# Copyright (c) 1993 - 2025 ARM Limited. All Rights Reserved.
# Use of this Software is subject to the terms and conditions of the
# applicable license agreement with ARM Limited.

# PhyVGen V 11.0.0-beta2
# ARM Version r3p1
# Creation Date: Fri Jan 31 07:21:36 2025


# Memory Configuration:
# ~~~~~~~~~~~~~~~~~~~~~
#  -PG_PINS_domain VDDCE -activity_factor 50 -atf off -back_biasing off
# -bit_blast off -bits 46 -bmux off -check_instname on -diodes on -drive 6 -ema
# on -frequency 500 -instname sram128x46 -left_bus_delim "[" -mux 2 -mvt BASE
# -name_case lower -power_gating off -power_type otc -pwr_gnd_rename
# vddpe:VDDPE,vddce:VDDCE,vsse:VSSE -rcols 2 -redundancy off -retention on
# -right_bus_delim "]" -rrows 0 -ser none -single_domain_only on -site_def off
# -top_layer m5-m10 -vmin_assist on -words 128 -wp_size 1 -write_mask off
# -write_thru off -corners
# ffg_cbestt_0p88v_0p88v_0c,ffg_cbestt_0p88v_0p88v_125c,ffg_cbestt_0p88v_0p88v_m40c,ssg_cworstt_0p72v_0p72v_0c,ssg_cworstt_0p72v_0p72v_125c,ssg_cworstt_0p72v_0p72v_m40c,tt_typical_0p80v_0p80v_25c,tt_typical_0p80v_0p80v_85c
# 

VERSION 5.8 ;
BUSBITCHARS "[]" ;
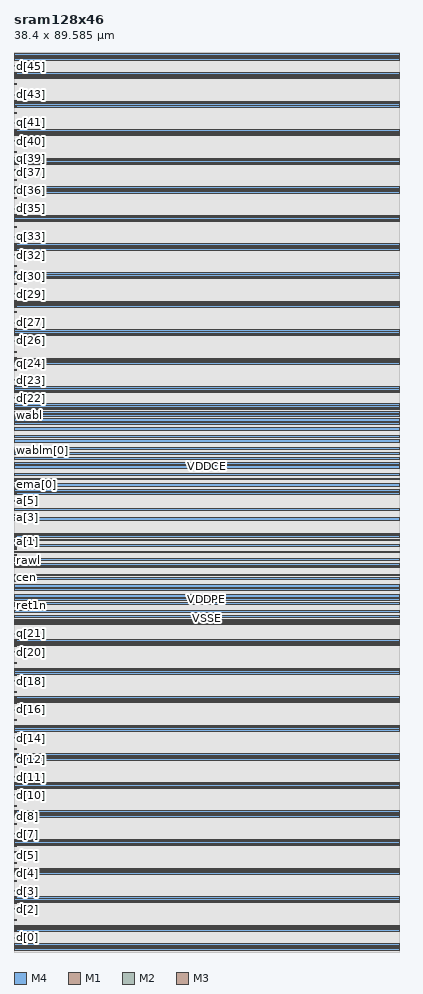
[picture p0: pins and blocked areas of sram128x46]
MACRO sram128x46
	FOREIGN sram128x46 0 0 ;
	SYMMETRY X Y ;
	SIZE 38.4 BY 89.585 ;
	CLASS BLOCK ;
	PIN VDDCE
		USE POWER ;
		DIRECTION INOUT ;
		PORT
			LAYER	M4 ;
			RECT	0 36.325 38.4 36.535 ;
		END

		PORT
			LAYER	M4 ;
			RECT	0 48.175 38.4 48.385 ;
		END

		PORT
			LAYER	M4 ;
			RECT	0 50.035 38.4 50.185 ;
		END

		PORT
			LAYER	M4 ;
			RECT	0 53.64 38.4 53.79 ;
		END

		PORT
			LAYER	M4 ;
			RECT	0 87.135 38.4 87.285 ;
		END

		PORT
			LAYER	M4 ;
			RECT	0 25.02 38.4 25.17 ;
		END

		PORT
			LAYER	M4 ;
			RECT	0 22.18 38.4 22.33 ;
		END

		PORT
			LAYER	M4 ;
			RECT	0 19.34 38.4 19.49 ;
		END

		PORT
			LAYER	M4 ;
			RECT	0 16.5 38.4 16.65 ;
		END

		PORT
			LAYER	M4 ;
			RECT	0 13.66 38.4 13.81 ;
		END

		PORT
			LAYER	M4 ;
			RECT	0 81.455 38.4 81.605 ;
		END

		PORT
			LAYER	M4 ;
			RECT	0 10.82 38.4 10.97 ;
		END

		PORT
			LAYER	M4 ;
			RECT	0 7.98 38.4 8.13 ;
		END

		PORT
			LAYER	M4 ;
			RECT	0 5.14 38.4 5.29 ;
		END

		PORT
			LAYER	M4 ;
			RECT	0 2.3 38.4 2.45 ;
		END

		PORT
			LAYER	M4 ;
			RECT	0 78.615 38.4 78.765 ;
		END

		PORT
			LAYER	M4 ;
			RECT	0 75.775 38.4 75.925 ;
		END

		PORT
			LAYER	M4 ;
			RECT	0 72.935 38.4 73.085 ;
		END

		PORT
			LAYER	M4 ;
			RECT	0 70.095 38.4 70.245 ;
		END

		PORT
			LAYER	M4 ;
			RECT	0 67.255 38.4 67.405 ;
		END

		PORT
			LAYER	M4 ;
			RECT	0 64.415 38.4 64.565 ;
		END

		PORT
			LAYER	M4 ;
			RECT	0 61.575 38.4 61.725 ;
		END

		PORT
			LAYER	M4 ;
			RECT	0 58.735 38.4 58.885 ;
		END

		PORT
			LAYER	M4 ;
			RECT	0 55.895 38.4 56.045 ;
		END

		PORT
			LAYER	M4 ;
			RECT	0 84.295 38.4 84.445 ;
		END

		PORT
			LAYER	M4 ;
			RECT	0 30.7 38.4 30.85 ;
		END

		PORT
			LAYER	M4 ;
			RECT	0 27.86 38.4 28.01 ;
		END

		PORT
			LAYER	M4 ;
			RECT	0 32.595 38.4 32.725 ;
		END

		PORT
			LAYER	M4 ;
			RECT	0 36.025 38.4 36.155 ;
		END

		PORT
			LAYER	M4 ;
			RECT	0 88.765 38.4 88.915 ;
		END

		PORT
			LAYER	M4 ;
			RECT	0 48.555 38.4 48.685 ;
		END

		PORT
			LAYER	M4 ;
			RECT	0 0.67 38.4 0.82 ;
		END

		PORT
			LAYER	M4 ;
			RECT	0 54.43 38.4 54.56 ;
		END

	END VDDCE

	PIN VDDPE
		USE POWER ;
		DIRECTION INOUT ;
		PORT
			LAYER	M4 ;
			RECT	0 34.615 38.4 34.765 ;
		END

		PORT
			LAYER	M4 ;
			RECT	0 34.985 38.4 35.195 ;
		END

		PORT
			LAYER	M4 ;
			RECT	0 38.51 38.4 38.72 ;
		END

		PORT
			LAYER	M4 ;
			RECT	0 38.985 38.4 39.195 ;
		END

		PORT
			LAYER	M4 ;
			RECT	0 40.4 38.4 40.61 ;
		END

		PORT
			LAYER	M4 ;
			RECT	0 41.545 38.4 41.695 ;
		END

		PORT
			LAYER	M4 ;
			RECT	0 43.96 38.4 44.17 ;
		END

		PORT
			LAYER	M4 ;
			RECT	0 45.52 38.4 45.73 ;
		END

		PORT
			LAYER	M4 ;
			RECT	0 46.38 38.4 46.59 ;
		END

		PORT
			LAYER	M4 ;
			RECT	0 49.49 38.4 49.7 ;
		END

		PORT
			LAYER	M4 ;
			RECT	0 52.47 38.4 52.68 ;
		END

		PORT
			LAYER	M4 ;
			RECT	0 52.845 38.4 53.055 ;
		END

		PORT
			LAYER	M4 ;
			RECT	0 86.905 38.4 87.055 ;
		END

		PORT
			LAYER	M4 ;
			RECT	0 25.25 38.4 25.4 ;
		END

		PORT
			LAYER	M4 ;
			RECT	0 22.41 38.4 22.56 ;
		END

		PORT
			LAYER	M4 ;
			RECT	0 19.57 38.4 19.72 ;
		END

		PORT
			LAYER	M4 ;
			RECT	0 16.73 38.4 16.88 ;
		END

		PORT
			LAYER	M4 ;
			RECT	0 13.89 38.4 14.04 ;
		END

		PORT
			LAYER	M4 ;
			RECT	0 11.05 38.4 11.2 ;
		END

		PORT
			LAYER	M4 ;
			RECT	0 8.21 38.4 8.36 ;
		END

		PORT
			LAYER	M4 ;
			RECT	0 81.225 38.4 81.375 ;
		END

		PORT
			LAYER	M4 ;
			RECT	0 5.37 38.4 5.52 ;
		END

		PORT
			LAYER	M4 ;
			RECT	0 2.53 38.4 2.68 ;
		END

		PORT
			LAYER	M4 ;
			RECT	0 78.385 38.4 78.535 ;
		END

		PORT
			LAYER	M4 ;
			RECT	0 75.545 38.4 75.695 ;
		END

		PORT
			LAYER	M4 ;
			RECT	0 72.705 38.4 72.855 ;
		END

		PORT
			LAYER	M4 ;
			RECT	0 69.865 38.4 70.015 ;
		END

		PORT
			LAYER	M4 ;
			RECT	0 67.025 38.4 67.175 ;
		END

		PORT
			LAYER	M4 ;
			RECT	0 64.185 38.4 64.335 ;
		END

		PORT
			LAYER	M4 ;
			RECT	0 61.345 38.4 61.495 ;
		END

		PORT
			LAYER	M4 ;
			RECT	0 58.505 38.4 58.655 ;
		END

		PORT
			LAYER	M4 ;
			RECT	0 55.665 38.4 55.815 ;
		END

		PORT
			LAYER	M4 ;
			RECT	0 84.065 38.4 84.215 ;
		END

		PORT
			LAYER	M4 ;
			RECT	0 30.93 38.4 31.08 ;
		END

		PORT
			LAYER	M4 ;
			RECT	0 28.09 38.4 28.24 ;
		END

		PORT
			LAYER	M4 ;
			RECT	0 89.265 38.4 89.415 ;
		END

		PORT
			LAYER	M4 ;
			RECT	0 33.015 38.4 33.145 ;
		END

		PORT
			LAYER	M4 ;
			RECT	0 37.485 38.4 37.615 ;
		END

		PORT
			LAYER	M4 ;
			RECT	0 0.17 38.4 0.32 ;
		END

		PORT
			LAYER	M4 ;
			RECT	0 45.86 38.4 45.99 ;
		END

		PORT
			LAYER	M4 ;
			RECT	0 54.01 38.4 54.14 ;
		END

	END VDDPE

	PIN VSSE
		USE GROUND ;
		DIRECTION INOUT ;
		PORT
			LAYER	M4 ;
			RECT	0 32.805 38.4 32.935 ;
		END

		PORT
			LAYER	M4 ;
			RECT	0 89.015 38.4 89.165 ;
		END

		PORT
			LAYER	M4 ;
			RECT	0 39.785 38.4 39.915 ;
		END

		PORT
			LAYER	M4 ;
			RECT	0 0.42 38.4 0.57 ;
		END

		PORT
			LAYER	M4 ;
			RECT	0 47.05 38.4 47.18 ;
		END

		PORT
			LAYER	M4 ;
			RECT	0 51.245 38.4 51.375 ;
		END

		PORT
			LAYER	M4 ;
			RECT	0 54.22 38.4 54.35 ;
		END

		PORT
			LAYER	M4 ;
			RECT	0 33.34 38.4 33.47 ;
		END

		PORT
			LAYER	M4 ;
			RECT	0 33.75 38.4 33.96 ;
		END

		PORT
			LAYER	M4 ;
			RECT	0 35.33 38.4 35.54 ;
		END

		PORT
			LAYER	M4 ;
			RECT	0 37.12 38.4 37.27 ;
		END

		PORT
			LAYER	M4 ;
			RECT	0 38.225 38.4 38.375 ;
		END

		PORT
			LAYER	M4 ;
			RECT	0 40.935 38.4 41.085 ;
		END

		PORT
			LAYER	M4 ;
			RECT	0 41.275 38.4 41.425 ;
		END

		PORT
			LAYER	M4 ;
			RECT	0 42.99 38.4 43.2 ;
		END

		PORT
			LAYER	M4 ;
			RECT	0 47.41 38.4 47.62 ;
		END

		PORT
			LAYER	M4 ;
			RECT	0 49.015 38.4 49.225 ;
		END

		PORT
			LAYER	M4 ;
			RECT	0 50.755 38.4 50.965 ;
		END

		PORT
			LAYER	M4 ;
			RECT	0 51.95 38.4 52.16 ;
		END

		PORT
			LAYER	M4 ;
			RECT	0 53.315 38.4 53.525 ;
		END

		PORT
			LAYER	M4 ;
			RECT	0 87.365 38.4 87.515 ;
		END

		PORT
			LAYER	M4 ;
			RECT	0 27.63 38.4 27.78 ;
		END

		PORT
			LAYER	M4 ;
			RECT	0 24.79 38.4 24.94 ;
		END

		PORT
			LAYER	M4 ;
			RECT	0 21.95 38.4 22.1 ;
		END

		PORT
			LAYER	M4 ;
			RECT	0 81.685 38.4 81.835 ;
		END

		PORT
			LAYER	M4 ;
			RECT	0 19.11 38.4 19.26 ;
		END

		PORT
			LAYER	M4 ;
			RECT	0 16.27 38.4 16.42 ;
		END

		PORT
			LAYER	M4 ;
			RECT	0 13.43 38.4 13.58 ;
		END

		PORT
			LAYER	M4 ;
			RECT	0 10.59 38.4 10.74 ;
		END

		PORT
			LAYER	M4 ;
			RECT	0 7.75 38.4 7.9 ;
		END

		PORT
			LAYER	M4 ;
			RECT	0 4.91 38.4 5.06 ;
		END

		PORT
			LAYER	M4 ;
			RECT	0 2.07 38.4 2.22 ;
		END

		PORT
			LAYER	M4 ;
			RECT	0 78.845 38.4 78.995 ;
		END

		PORT
			LAYER	M4 ;
			RECT	0 76.005 38.4 76.155 ;
		END

		PORT
			LAYER	M4 ;
			RECT	0 73.165 38.4 73.315 ;
		END

		PORT
			LAYER	M4 ;
			RECT	0 70.325 38.4 70.475 ;
		END

		PORT
			LAYER	M4 ;
			RECT	0 67.485 38.4 67.635 ;
		END

		PORT
			LAYER	M4 ;
			RECT	0 64.645 38.4 64.795 ;
		END

		PORT
			LAYER	M4 ;
			RECT	0 61.805 38.4 61.955 ;
		END

		PORT
			LAYER	M4 ;
			RECT	0 58.965 38.4 59.115 ;
		END

		PORT
			LAYER	M4 ;
			RECT	0 56.125 38.4 56.275 ;
		END

		PORT
			LAYER	M4 ;
			RECT	0 84.525 38.4 84.675 ;
		END

		PORT
			LAYER	M4 ;
			RECT	0 30.47 38.4 30.62 ;
		END

	END VSSE

	PIN a[0]
		USE SIGNAL ;
		DIRECTION INPUT ;
		SHAPE ABUTMENT ;
		PORT
			LAYER	M1 ;
			RECT	0 52.745 0.25 52.845 ;
			LAYER	M2 ;
			RECT	0 52.745 0.25 52.845 ;
			LAYER	M3 ;
			RECT	0 52.745 0.25 52.845 ;
		END

		ANTENNAGATEAREA 0.014 ;
		ANTENNADIFFAREA 0.018 ;
		ANTENNAPARTIALMETALAREA 0.025 ;
	END a[0]

	PIN a[1]
		USE SIGNAL ;
		DIRECTION INPUT ;
		SHAPE ABUTMENT ;
		PORT
			LAYER	M1 ;
			RECT	0 40.85 0.25 40.95 ;
			LAYER	M2 ;
			RECT	0 40.85 0.25 40.95 ;
			LAYER	M3 ;
			RECT	0 40.85 0.25 40.95 ;
		END

		ANTENNAGATEAREA 0.014 ;
		ANTENNADIFFAREA 0.018 ;
		ANTENNAPARTIALMETALAREA 0.025 ;
	END a[1]

	PIN a[2]
		USE SIGNAL ;
		DIRECTION INPUT ;
		SHAPE ABUTMENT ;
		PORT
			LAYER	M1 ;
			RECT	0 41.25 0.25 41.35 ;
			LAYER	M2 ;
			RECT	0 41.25 0.25 41.35 ;
			LAYER	M3 ;
			RECT	0 41.25 0.25 41.35 ;
		END

		ANTENNAGATEAREA 0.014 ;
		ANTENNADIFFAREA 0.018 ;
		ANTENNAPARTIALMETALAREA 0.025 ;
	END a[2]

	PIN a[3]
		USE SIGNAL ;
		DIRECTION INPUT ;
		SHAPE ABUTMENT ;
		PORT
			LAYER	M1 ;
			RECT	0 43.16 0.25 43.26 ;
			LAYER	M2 ;
			RECT	0 43.16 0.25 43.26 ;
			LAYER	M3 ;
			RECT	0 43.16 0.25 43.26 ;
		END

		ANTENNAGATEAREA 0.014 ;
		ANTENNADIFFAREA 0.018 ;
		ANTENNAPARTIALMETALAREA 0.025 ;
	END a[3]

	PIN a[4]
		USE SIGNAL ;
		DIRECTION INPUT ;
		SHAPE ABUTMENT ;
		PORT
			LAYER	M1 ;
			RECT	0 43.49 0.25 43.59 ;
			LAYER	M2 ;
			RECT	0 43.49 0.25 43.59 ;
			LAYER	M3 ;
			RECT	0 43.49 0.25 43.59 ;
		END

		ANTENNAGATEAREA 0.014 ;
		ANTENNADIFFAREA 0.018 ;
		ANTENNAPARTIALMETALAREA 0.025 ;
	END a[4]

	PIN a[5]
		USE SIGNAL ;
		DIRECTION INPUT ;
		SHAPE ABUTMENT ;
		PORT
			LAYER	M1 ;
			RECT	0 45.595 0.25 45.695 ;
			LAYER	M2 ;
			RECT	0 45.595 0.25 45.695 ;
			LAYER	M3 ;
			RECT	0 45.595 0.25 45.695 ;
		END

		ANTENNAGATEAREA 0.014 ;
		ANTENNADIFFAREA 0.018 ;
		ANTENNAPARTIALMETALAREA 0.025 ;
	END a[5]

	PIN a[6]
		USE SIGNAL ;
		DIRECTION INPUT ;
		SHAPE ABUTMENT ;
		PORT
			LAYER	M1 ;
			RECT	0 46.865 0.25 46.965 ;
			LAYER	M2 ;
			RECT	0 46.865 0.25 46.965 ;
			LAYER	M3 ;
			RECT	0 46.865 0.25 46.965 ;
		END

		ANTENNAGATEAREA 0.014 ;
		ANTENNADIFFAREA 0.018 ;
		ANTENNAPARTIALMETALAREA 0.025 ;
	END a[6]

	PIN cen
		USE SIGNAL ;
		DIRECTION INPUT ;
		SHAPE ABUTMENT ;
		PORT
			LAYER	M1 ;
			RECT	0 37.26 0.25 37.36 ;
			LAYER	M2 ;
			RECT	0 37.26 0.25 37.36 ;
			LAYER	M3 ;
			RECT	0 37.26 0.25 37.36 ;
		END

		ANTENNAGATEAREA 0.014 ;
		ANTENNADIFFAREA 0.018 ;
		ANTENNAPARTIALMETALAREA 0.025 ;
	END cen

	PIN clk
		USE SIGNAL ;
		DIRECTION INPUT ;
		SHAPE ABUTMENT ;
		PORT
			LAYER	M1 ;
			RECT	0 36.87 0.25 36.97 ;
			LAYER	M2 ;
			RECT	0 36.87 0.25 36.97 ;
			LAYER	M3 ;
			RECT	0 36.87 0.25 36.97 ;
			LAYER	M4 ;
			RECT	0 36.87 0.25 36.97 ;
		END

		ANTENNAGATEAREA 0.014 ;
		ANTENNADIFFAREA 0.018 ;
		ANTENNAPARTIALMETALAREA 0.025 ;
	END clk

	PIN d[0]
		USE SIGNAL ;
		DIRECTION INPUT ;
		SHAPE ABUTMENT ;
		PORT
			LAYER	M1 ;
			RECT	0 1.365 0.25 1.465 ;
			LAYER	M2 ;
			RECT	0 1.365 0.25 1.465 ;
			LAYER	M3 ;
			RECT	0 1.365 0.25 1.465 ;
		END

		ANTENNAGATEAREA 0.014 ;
		ANTENNADIFFAREA 0.018 ;
		ANTENNAPARTIALMETALAREA 0.025 ;
	END d[0]

	PIN d[10]
		USE SIGNAL ;
		DIRECTION INPUT ;
		SHAPE ABUTMENT ;
		PORT
			LAYER	M1 ;
			RECT	0 15.565 0.25 15.665 ;
			LAYER	M2 ;
			RECT	0 15.565 0.25 15.665 ;
			LAYER	M3 ;
			RECT	0 15.565 0.25 15.665 ;
		END

		ANTENNAGATEAREA 0.014 ;
		ANTENNADIFFAREA 0.018 ;
		ANTENNAPARTIALMETALAREA 0.025 ;
	END d[10]

	PIN d[11]
		USE SIGNAL ;
		DIRECTION INPUT ;
		SHAPE ABUTMENT ;
		PORT
			LAYER	M1 ;
			RECT	0 17.355 0.25 17.455 ;
			LAYER	M2 ;
			RECT	0 17.355 0.25 17.455 ;
			LAYER	M3 ;
			RECT	0 17.355 0.25 17.455 ;
		END

		ANTENNAGATEAREA 0.014 ;
		ANTENNADIFFAREA 0.018 ;
		ANTENNAPARTIALMETALAREA 0.025 ;
	END d[11]

	PIN d[12]
		USE SIGNAL ;
		DIRECTION INPUT ;
		SHAPE ABUTMENT ;
		PORT
			LAYER	M1 ;
			RECT	0 18.405 0.25 18.505 ;
			LAYER	M2 ;
			RECT	0 18.405 0.25 18.505 ;
			LAYER	M3 ;
			RECT	0 18.405 0.25 18.505 ;
		END

		ANTENNAGATEAREA 0.014 ;
		ANTENNADIFFAREA 0.018 ;
		ANTENNAPARTIALMETALAREA 0.025 ;
	END d[12]

	PIN d[13]
		USE SIGNAL ;
		DIRECTION INPUT ;
		SHAPE ABUTMENT ;
		PORT
			LAYER	M1 ;
			RECT	0 20.195 0.25 20.295 ;
			LAYER	M2 ;
			RECT	0 20.195 0.25 20.295 ;
			LAYER	M3 ;
			RECT	0 20.195 0.25 20.295 ;
		END

		ANTENNAGATEAREA 0.014 ;
		ANTENNADIFFAREA 0.018 ;
		ANTENNAPARTIALMETALAREA 0.025 ;
	END d[13]

	PIN d[14]
		USE SIGNAL ;
		DIRECTION INPUT ;
		SHAPE ABUTMENT ;
		PORT
			LAYER	M1 ;
			RECT	0 21.245 0.25 21.345 ;
			LAYER	M2 ;
			RECT	0 21.245 0.25 21.345 ;
			LAYER	M3 ;
			RECT	0 21.245 0.25 21.345 ;
		END

		ANTENNAGATEAREA 0.014 ;
		ANTENNADIFFAREA 0.018 ;
		ANTENNAPARTIALMETALAREA 0.025 ;
	END d[14]

	PIN d[15]
		USE SIGNAL ;
		DIRECTION INPUT ;
		SHAPE ABUTMENT ;
		PORT
			LAYER	M1 ;
			RECT	0 23.035 0.25 23.135 ;
			LAYER	M2 ;
			RECT	0 23.035 0.25 23.135 ;
			LAYER	M3 ;
			RECT	0 23.035 0.25 23.135 ;
		END

		ANTENNAGATEAREA 0.014 ;
		ANTENNADIFFAREA 0.018 ;
		ANTENNAPARTIALMETALAREA 0.025 ;
	END d[15]

	PIN d[16]
		USE SIGNAL ;
		DIRECTION INPUT ;
		SHAPE ABUTMENT ;
		PORT
			LAYER	M1 ;
			RECT	0 24.085 0.25 24.185 ;
			LAYER	M2 ;
			RECT	0 24.085 0.25 24.185 ;
			LAYER	M3 ;
			RECT	0 24.085 0.25 24.185 ;
		END

		ANTENNAGATEAREA 0.014 ;
		ANTENNADIFFAREA 0.018 ;
		ANTENNAPARTIALMETALAREA 0.025 ;
	END d[16]

	PIN d[17]
		USE SIGNAL ;
		DIRECTION INPUT ;
		SHAPE ABUTMENT ;
		PORT
			LAYER	M1 ;
			RECT	0 25.875 0.25 25.975 ;
			LAYER	M2 ;
			RECT	0 25.875 0.25 25.975 ;
			LAYER	M3 ;
			RECT	0 25.875 0.25 25.975 ;
		END

		ANTENNAGATEAREA 0.014 ;
		ANTENNADIFFAREA 0.018 ;
		ANTENNAPARTIALMETALAREA 0.025 ;
	END d[17]

	PIN d[18]
		USE SIGNAL ;
		DIRECTION INPUT ;
		SHAPE ABUTMENT ;
		PORT
			LAYER	M1 ;
			RECT	0 26.925 0.25 27.025 ;
			LAYER	M2 ;
			RECT	0 26.925 0.25 27.025 ;
			LAYER	M3 ;
			RECT	0 26.925 0.25 27.025 ;
		END

		ANTENNAGATEAREA 0.014 ;
		ANTENNADIFFAREA 0.018 ;
		ANTENNAPARTIALMETALAREA 0.025 ;
	END d[18]

	PIN d[19]
		USE SIGNAL ;
		DIRECTION INPUT ;
		SHAPE ABUTMENT ;
		PORT
			LAYER	M1 ;
			RECT	0 28.715 0.25 28.815 ;
			LAYER	M2 ;
			RECT	0 28.715 0.25 28.815 ;
			LAYER	M3 ;
			RECT	0 28.715 0.25 28.815 ;
		END

		ANTENNAGATEAREA 0.014 ;
		ANTENNADIFFAREA 0.018 ;
		ANTENNAPARTIALMETALAREA 0.025 ;
	END d[19]

	PIN d[1]
		USE SIGNAL ;
		DIRECTION INPUT ;
		SHAPE ABUTMENT ;
		PORT
			LAYER	M1 ;
			RECT	0 3.155 0.25 3.255 ;
			LAYER	M2 ;
			RECT	0 3.155 0.25 3.255 ;
			LAYER	M3 ;
			RECT	0 3.155 0.25 3.255 ;
		END

		ANTENNAGATEAREA 0.014 ;
		ANTENNADIFFAREA 0.018 ;
		ANTENNAPARTIALMETALAREA 0.025 ;
	END d[1]

	PIN d[20]
		USE SIGNAL ;
		DIRECTION INPUT ;
		SHAPE ABUTMENT ;
		PORT
			LAYER	M1 ;
			RECT	0 29.765 0.25 29.865 ;
			LAYER	M2 ;
			RECT	0 29.765 0.25 29.865 ;
			LAYER	M3 ;
			RECT	0 29.765 0.25 29.865 ;
		END

		ANTENNAGATEAREA 0.014 ;
		ANTENNADIFFAREA 0.018 ;
		ANTENNAPARTIALMETALAREA 0.025 ;
	END d[20]

	PIN d[21]
		USE SIGNAL ;
		DIRECTION INPUT ;
		SHAPE ABUTMENT ;
		PORT
			LAYER	M1 ;
			RECT	0 31.555 0.25 31.655 ;
			LAYER	M2 ;
			RECT	0 31.555 0.25 31.655 ;
			LAYER	M3 ;
			RECT	0 31.555 0.25 31.655 ;
		END

		ANTENNAGATEAREA 0.014 ;
		ANTENNADIFFAREA 0.018 ;
		ANTENNAPARTIALMETALAREA 0.025 ;
	END d[21]

	PIN d[22]
		USE SIGNAL ;
		DIRECTION INPUT ;
		SHAPE ABUTMENT ;
		PORT
			LAYER	M1 ;
			RECT	0 55.09 0.25 55.19 ;
			LAYER	M2 ;
			RECT	0 55.09 0.25 55.19 ;
			LAYER	M3 ;
			RECT	0 55.09 0.25 55.19 ;
		END

		ANTENNAGATEAREA 0.014 ;
		ANTENNADIFFAREA 0.018 ;
		ANTENNAPARTIALMETALAREA 0.025 ;
	END d[22]

	PIN d[23]
		USE SIGNAL ;
		DIRECTION INPUT ;
		SHAPE ABUTMENT ;
		PORT
			LAYER	M1 ;
			RECT	0 56.88 0.25 56.98 ;
			LAYER	M2 ;
			RECT	0 56.88 0.25 56.98 ;
			LAYER	M3 ;
			RECT	0 56.88 0.25 56.98 ;
		END

		ANTENNAGATEAREA 0.014 ;
		ANTENNADIFFAREA 0.018 ;
		ANTENNAPARTIALMETALAREA 0.025 ;
	END d[23]

	PIN d[24]
		USE SIGNAL ;
		DIRECTION INPUT ;
		SHAPE ABUTMENT ;
		PORT
			LAYER	M1 ;
			RECT	0 57.93 0.25 58.03 ;
			LAYER	M2 ;
			RECT	0 57.93 0.25 58.03 ;
			LAYER	M3 ;
			RECT	0 57.93 0.25 58.03 ;
		END

		ANTENNAGATEAREA 0.014 ;
		ANTENNADIFFAREA 0.018 ;
		ANTENNAPARTIALMETALAREA 0.025 ;
	END d[24]

	PIN d[25]
		USE SIGNAL ;
		DIRECTION INPUT ;
		SHAPE ABUTMENT ;
		PORT
			LAYER	M1 ;
			RECT	0 59.72 0.25 59.82 ;
			LAYER	M2 ;
			RECT	0 59.72 0.25 59.82 ;
			LAYER	M3 ;
			RECT	0 59.72 0.25 59.82 ;
		END

		ANTENNAGATEAREA 0.014 ;
		ANTENNADIFFAREA 0.018 ;
		ANTENNAPARTIALMETALAREA 0.025 ;
	END d[25]

	PIN d[26]
		USE SIGNAL ;
		DIRECTION INPUT ;
		SHAPE ABUTMENT ;
		PORT
			LAYER	M1 ;
			RECT	0 60.77 0.25 60.87 ;
			LAYER	M2 ;
			RECT	0 60.77 0.25 60.87 ;
			LAYER	M3 ;
			RECT	0 60.77 0.25 60.87 ;
		END

		ANTENNAGATEAREA 0.014 ;
		ANTENNADIFFAREA 0.018 ;
		ANTENNAPARTIALMETALAREA 0.025 ;
	END d[26]

	PIN d[27]
		USE SIGNAL ;
		DIRECTION INPUT ;
		SHAPE ABUTMENT ;
		PORT
			LAYER	M1 ;
			RECT	0 62.56 0.25 62.66 ;
			LAYER	M2 ;
			RECT	0 62.56 0.25 62.66 ;
			LAYER	M3 ;
			RECT	0 62.56 0.25 62.66 ;
		END

		ANTENNAGATEAREA 0.014 ;
		ANTENNADIFFAREA 0.018 ;
		ANTENNAPARTIALMETALAREA 0.025 ;
	END d[27]

	PIN d[28]
		USE SIGNAL ;
		DIRECTION INPUT ;
		SHAPE ABUTMENT ;
		PORT
			LAYER	M1 ;
			RECT	0 63.61 0.25 63.71 ;
			LAYER	M2 ;
			RECT	0 63.61 0.25 63.71 ;
			LAYER	M3 ;
			RECT	0 63.61 0.25 63.71 ;
		END

		ANTENNAGATEAREA 0.014 ;
		ANTENNADIFFAREA 0.018 ;
		ANTENNAPARTIALMETALAREA 0.025 ;
	END d[28]

	PIN d[29]
		USE SIGNAL ;
		DIRECTION INPUT ;
		SHAPE ABUTMENT ;
		PORT
			LAYER	M1 ;
			RECT	0 65.4 0.25 65.5 ;
			LAYER	M2 ;
			RECT	0 65.4 0.25 65.5 ;
			LAYER	M3 ;
			RECT	0 65.4 0.25 65.5 ;
		END

		ANTENNAGATEAREA 0.014 ;
		ANTENNADIFFAREA 0.018 ;
		ANTENNAPARTIALMETALAREA 0.025 ;
	END d[29]

	PIN d[2]
		USE SIGNAL ;
		DIRECTION INPUT ;
		SHAPE ABUTMENT ;
		PORT
			LAYER	M1 ;
			RECT	0 4.205 0.25 4.305 ;
			LAYER	M2 ;
			RECT	0 4.205 0.25 4.305 ;
			LAYER	M3 ;
			RECT	0 4.205 0.25 4.305 ;
		END

		ANTENNAGATEAREA 0.014 ;
		ANTENNADIFFAREA 0.018 ;
		ANTENNAPARTIALMETALAREA 0.025 ;
	END d[2]

	PIN d[30]
		USE SIGNAL ;
		DIRECTION INPUT ;
		SHAPE ABUTMENT ;
		PORT
			LAYER	M1 ;
			RECT	0 66.45 0.25 66.55 ;
			LAYER	M2 ;
			RECT	0 66.45 0.25 66.55 ;
			LAYER	M3 ;
			RECT	0 66.45 0.25 66.55 ;
		END

		ANTENNAGATEAREA 0.014 ;
		ANTENNADIFFAREA 0.018 ;
		ANTENNAPARTIALMETALAREA 0.025 ;
	END d[30]

	PIN d[31]
		USE SIGNAL ;
		DIRECTION INPUT ;
		SHAPE ABUTMENT ;
		PORT
			LAYER	M1 ;
			RECT	0 68.24 0.25 68.34 ;
			LAYER	M2 ;
			RECT	0 68.24 0.25 68.34 ;
			LAYER	M3 ;
			RECT	0 68.24 0.25 68.34 ;
		END

		ANTENNAGATEAREA 0.014 ;
		ANTENNADIFFAREA 0.018 ;
		ANTENNAPARTIALMETALAREA 0.025 ;
	END d[31]

	PIN d[32]
		USE SIGNAL ;
		DIRECTION INPUT ;
		SHAPE ABUTMENT ;
		PORT
			LAYER	M1 ;
			RECT	0 69.29 0.25 69.39 ;
			LAYER	M2 ;
			RECT	0 69.29 0.25 69.39 ;
			LAYER	M3 ;
			RECT	0 69.29 0.25 69.39 ;
		END

		ANTENNAGATEAREA 0.014 ;
		ANTENNADIFFAREA 0.018 ;
		ANTENNAPARTIALMETALAREA 0.025 ;
	END d[32]

	PIN d[33]
		USE SIGNAL ;
		DIRECTION INPUT ;
		SHAPE ABUTMENT ;
		PORT
			LAYER	M1 ;
			RECT	0 71.08 0.25 71.18 ;
			LAYER	M2 ;
			RECT	0 71.08 0.25 71.18 ;
			LAYER	M3 ;
			RECT	0 71.08 0.25 71.18 ;
		END

		ANTENNAGATEAREA 0.014 ;
		ANTENNADIFFAREA 0.018 ;
		ANTENNAPARTIALMETALAREA 0.025 ;
	END d[33]

	PIN d[34]
		USE SIGNAL ;
		DIRECTION INPUT ;
		SHAPE ABUTMENT ;
		PORT
			LAYER	M1 ;
			RECT	0 72.13 0.25 72.23 ;
			LAYER	M2 ;
			RECT	0 72.13 0.25 72.23 ;
			LAYER	M3 ;
			RECT	0 72.13 0.25 72.23 ;
		END

		ANTENNAGATEAREA 0.014 ;
		ANTENNADIFFAREA 0.018 ;
		ANTENNAPARTIALMETALAREA 0.025 ;
	END d[34]

	PIN d[35]
		USE SIGNAL ;
		DIRECTION INPUT ;
		SHAPE ABUTMENT ;
		PORT
			LAYER	M1 ;
			RECT	0 73.92 0.25 74.02 ;
			LAYER	M2 ;
			RECT	0 73.92 0.25 74.02 ;
			LAYER	M3 ;
			RECT	0 73.92 0.25 74.02 ;
		END

		ANTENNAGATEAREA 0.014 ;
		ANTENNADIFFAREA 0.018 ;
		ANTENNAPARTIALMETALAREA 0.025 ;
	END d[35]

	PIN d[36]
		USE SIGNAL ;
		DIRECTION INPUT ;
		SHAPE ABUTMENT ;
		PORT
			LAYER	M1 ;
			RECT	0 74.97 0.25 75.07 ;
			LAYER	M2 ;
			RECT	0 74.97 0.25 75.07 ;
			LAYER	M3 ;
			RECT	0 74.97 0.25 75.07 ;
		END

		ANTENNAGATEAREA 0.014 ;
		ANTENNADIFFAREA 0.018 ;
		ANTENNAPARTIALMETALAREA 0.025 ;
	END d[36]

	PIN d[37]
		USE SIGNAL ;
		DIRECTION INPUT ;
		SHAPE ABUTMENT ;
		PORT
			LAYER	M1 ;
			RECT	0 76.76 0.25 76.86 ;
			LAYER	M2 ;
			RECT	0 76.76 0.25 76.86 ;
			LAYER	M3 ;
			RECT	0 76.76 0.25 76.86 ;
		END

		ANTENNAGATEAREA 0.014 ;
		ANTENNADIFFAREA 0.018 ;
		ANTENNAPARTIALMETALAREA 0.025 ;
	END d[37]

	PIN d[38]
		USE SIGNAL ;
		DIRECTION INPUT ;
		SHAPE ABUTMENT ;
		PORT
			LAYER	M1 ;
			RECT	0 77.81 0.25 77.91 ;
			LAYER	M2 ;
			RECT	0 77.81 0.25 77.91 ;
			LAYER	M3 ;
			RECT	0 77.81 0.25 77.91 ;
		END

		ANTENNAGATEAREA 0.014 ;
		ANTENNADIFFAREA 0.018 ;
		ANTENNAPARTIALMETALAREA 0.025 ;
	END d[38]

	PIN d[39]
		USE SIGNAL ;
		DIRECTION INPUT ;
		SHAPE ABUTMENT ;
		PORT
			LAYER	M1 ;
			RECT	0 79.6 0.25 79.7 ;
			LAYER	M2 ;
			RECT	0 79.6 0.25 79.7 ;
			LAYER	M3 ;
			RECT	0 79.6 0.25 79.7 ;
		END

		ANTENNAGATEAREA 0.014 ;
		ANTENNADIFFAREA 0.018 ;
		ANTENNAPARTIALMETALAREA 0.025 ;
	END d[39]

	PIN d[3]
		USE SIGNAL ;
		DIRECTION INPUT ;
		SHAPE ABUTMENT ;
		PORT
			LAYER	M1 ;
			RECT	0 5.995 0.25 6.095 ;
			LAYER	M2 ;
			RECT	0 5.995 0.25 6.095 ;
			LAYER	M3 ;
			RECT	0 5.995 0.25 6.095 ;
		END

		ANTENNAGATEAREA 0.014 ;
		ANTENNADIFFAREA 0.018 ;
		ANTENNAPARTIALMETALAREA 0.025 ;
	END d[3]

	PIN d[40]
		USE SIGNAL ;
		DIRECTION INPUT ;
		SHAPE ABUTMENT ;
		PORT
			LAYER	M1 ;
			RECT	0 80.65 0.25 80.75 ;
			LAYER	M2 ;
			RECT	0 80.65 0.25 80.75 ;
			LAYER	M3 ;
			RECT	0 80.65 0.25 80.75 ;
		END

		ANTENNAGATEAREA 0.014 ;
		ANTENNADIFFAREA 0.018 ;
		ANTENNAPARTIALMETALAREA 0.025 ;
	END d[40]

	PIN d[41]
		USE SIGNAL ;
		DIRECTION INPUT ;
		SHAPE ABUTMENT ;
		PORT
			LAYER	M1 ;
			RECT	0 82.44 0.25 82.54 ;
			LAYER	M2 ;
			RECT	0 82.44 0.25 82.54 ;
			LAYER	M3 ;
			RECT	0 82.44 0.25 82.54 ;
		END

		ANTENNAGATEAREA 0.014 ;
		ANTENNADIFFAREA 0.018 ;
		ANTENNAPARTIALMETALAREA 0.025 ;
	END d[41]

	PIN d[42]
		USE SIGNAL ;
		DIRECTION INPUT ;
		SHAPE ABUTMENT ;
		PORT
			LAYER	M1 ;
			RECT	0 83.49 0.25 83.59 ;
			LAYER	M2 ;
			RECT	0 83.49 0.25 83.59 ;
			LAYER	M3 ;
			RECT	0 83.49 0.25 83.59 ;
		END

		ANTENNAGATEAREA 0.014 ;
		ANTENNADIFFAREA 0.018 ;
		ANTENNAPARTIALMETALAREA 0.025 ;
	END d[42]

	PIN d[43]
		USE SIGNAL ;
		DIRECTION INPUT ;
		SHAPE ABUTMENT ;
		PORT
			LAYER	M1 ;
			RECT	0 85.28 0.25 85.38 ;
			LAYER	M2 ;
			RECT	0 85.28 0.25 85.38 ;
			LAYER	M3 ;
			RECT	0 85.28 0.25 85.38 ;
		END

		ANTENNAGATEAREA 0.014 ;
		ANTENNADIFFAREA 0.018 ;
		ANTENNAPARTIALMETALAREA 0.025 ;
	END d[43]

	PIN d[44]
		USE SIGNAL ;
		DIRECTION INPUT ;
		SHAPE ABUTMENT ;
		PORT
			LAYER	M1 ;
			RECT	0 86.33 0.25 86.43 ;
			LAYER	M2 ;
			RECT	0 86.33 0.25 86.43 ;
			LAYER	M3 ;
			RECT	0 86.33 0.25 86.43 ;
		END

		ANTENNAGATEAREA 0.014 ;
		ANTENNADIFFAREA 0.018 ;
		ANTENNAPARTIALMETALAREA 0.025 ;
	END d[44]

	PIN d[45]
		USE SIGNAL ;
		DIRECTION INPUT ;
		SHAPE ABUTMENT ;
		PORT
			LAYER	M1 ;
			RECT	0 88.12 0.25 88.22 ;
			LAYER	M2 ;
			RECT	0 88.12 0.25 88.22 ;
			LAYER	M3 ;
			RECT	0 88.12 0.25 88.22 ;
		END

		ANTENNAGATEAREA 0.014 ;
		ANTENNADIFFAREA 0.018 ;
		ANTENNAPARTIALMETALAREA 0.025 ;
	END d[45]

	PIN d[4]
		USE SIGNAL ;
		DIRECTION INPUT ;
		SHAPE ABUTMENT ;
		PORT
			LAYER	M1 ;
			RECT	0 7.045 0.25 7.145 ;
			LAYER	M2 ;
			RECT	0 7.045 0.25 7.145 ;
			LAYER	M3 ;
			RECT	0 7.045 0.25 7.145 ;
		END

		ANTENNAGATEAREA 0.014 ;
		ANTENNADIFFAREA 0.018 ;
		ANTENNAPARTIALMETALAREA 0.025 ;
	END d[4]

	PIN d[5]
		USE SIGNAL ;
		DIRECTION INPUT ;
		SHAPE ABUTMENT ;
		PORT
			LAYER	M1 ;
			RECT	0 8.835 0.25 8.935 ;
			LAYER	M2 ;
			RECT	0 8.835 0.25 8.935 ;
			LAYER	M3 ;
			RECT	0 8.835 0.25 8.935 ;
		END

		ANTENNAGATEAREA 0.014 ;
		ANTENNADIFFAREA 0.018 ;
		ANTENNAPARTIALMETALAREA 0.025 ;
	END d[5]

	PIN d[6]
		USE SIGNAL ;
		DIRECTION INPUT ;
		SHAPE ABUTMENT ;
		PORT
			LAYER	M1 ;
			RECT	0 9.885 0.25 9.985 ;
			LAYER	M2 ;
			RECT	0 9.885 0.25 9.985 ;
			LAYER	M3 ;
			RECT	0 9.885 0.25 9.985 ;
		END

		ANTENNAGATEAREA 0.014 ;
		ANTENNADIFFAREA 0.018 ;
		ANTENNAPARTIALMETALAREA 0.025 ;
	END d[6]

	PIN d[7]
		USE SIGNAL ;
		DIRECTION INPUT ;
		SHAPE ABUTMENT ;
		PORT
			LAYER	M1 ;
			RECT	0 11.675 0.25 11.775 ;
			LAYER	M2 ;
			RECT	0 11.675 0.25 11.775 ;
			LAYER	M3 ;
			RECT	0 11.675 0.25 11.775 ;
		END

		ANTENNAGATEAREA 0.014 ;
		ANTENNADIFFAREA 0.018 ;
		ANTENNAPARTIALMETALAREA 0.025 ;
	END d[7]

	PIN d[8]
		USE SIGNAL ;
		DIRECTION INPUT ;
		SHAPE ABUTMENT ;
		PORT
			LAYER	M1 ;
			RECT	0 12.725 0.25 12.825 ;
			LAYER	M2 ;
			RECT	0 12.725 0.25 12.825 ;
			LAYER	M3 ;
			RECT	0 12.725 0.25 12.825 ;
		END

		ANTENNAGATEAREA 0.014 ;
		ANTENNADIFFAREA 0.018 ;
		ANTENNAPARTIALMETALAREA 0.025 ;
	END d[8]

	PIN d[9]
		USE SIGNAL ;
		DIRECTION INPUT ;
		SHAPE ABUTMENT ;
		PORT
			LAYER	M1 ;
			RECT	0 14.515 0.25 14.615 ;
			LAYER	M2 ;
			RECT	0 14.515 0.25 14.615 ;
			LAYER	M3 ;
			RECT	0 14.515 0.25 14.615 ;
		END

		ANTENNAGATEAREA 0.014 ;
		ANTENNADIFFAREA 0.018 ;
		ANTENNAPARTIALMETALAREA 0.025 ;
	END d[9]

	PIN ema[0]
		USE SIGNAL ;
		DIRECTION INPUT ;
		SHAPE ABUTMENT ;
		PORT
			LAYER	M1 ;
			RECT	0 46.465 0.25 46.565 ;
			LAYER	M2 ;
			RECT	0 46.465 0.25 46.565 ;
			LAYER	M3 ;
			RECT	0 46.465 0.25 46.565 ;
		END

		ANTENNAGATEAREA 0.014 ;
		ANTENNADIFFAREA 0.018 ;
		ANTENNAPARTIALMETALAREA 0.025 ;
	END ema[0]

	PIN ema[1]
		USE SIGNAL ;
		DIRECTION INPUT ;
		SHAPE ABUTMENT ;
		PORT
			LAYER	M1 ;
			RECT	0 46.265 0.25 46.365 ;
			LAYER	M2 ;
			RECT	0 46.265 0.25 46.365 ;
			LAYER	M3 ;
			RECT	0 46.265 0.25 46.365 ;
		END

		ANTENNAGATEAREA 0.014 ;
		ANTENNADIFFAREA 0.018 ;
		ANTENNAPARTIALMETALAREA 0.025 ;
	END ema[1]

	PIN ema[2]
		USE SIGNAL ;
		DIRECTION INPUT ;
		SHAPE ABUTMENT ;
		PORT
			LAYER	M1 ;
			RECT	0 46.065 0.25 46.165 ;
			LAYER	M2 ;
			RECT	0 46.065 0.25 46.165 ;
			LAYER	M3 ;
			RECT	0 46.065 0.25 46.165 ;
		END

		ANTENNAGATEAREA 0.014 ;
		ANTENNADIFFAREA 0.018 ;
		ANTENNAPARTIALMETALAREA 0.025 ;
	END ema[2]

	PIN emas
		USE SIGNAL ;
		DIRECTION INPUT ;
		SHAPE ABUTMENT ;
		PORT
			LAYER	M1 ;
			RECT	0 53.12 0.25 53.22 ;
			LAYER	M2 ;
			RECT	0 53.12 0.25 53.22 ;
			LAYER	M3 ;
			RECT	0 53.12 0.25 53.22 ;
		END

		ANTENNAGATEAREA 0.014 ;
		ANTENNADIFFAREA 0.018 ;
		ANTENNAPARTIALMETALAREA 0.025 ;
	END emas

	PIN emaw[0]
		USE SIGNAL ;
		DIRECTION INPUT ;
		SHAPE ABUTMENT ;
		PORT
			LAYER	M2 ;
			RECT	0 40.055 0.25 40.155 ;
			LAYER	M3 ;
			RECT	0 40.055 0.25 40.155 ;
		END

		ANTENNAGATEAREA 0.014 ;
		ANTENNADIFFAREA 0.018 ;
		ANTENNAPARTIALMETALAREA 0.025 ;
	END emaw[0]

	PIN emaw[1]
		USE SIGNAL ;
		DIRECTION INPUT ;
		SHAPE ABUTMENT ;
		PORT
			LAYER	M1 ;
			RECT	0 40.25 0.25 40.35 ;
			LAYER	M2 ;
			RECT	0 40.25 0.25 40.35 ;
			LAYER	M3 ;
			RECT	0 40.25 0.25 40.35 ;
		END

		ANTENNAGATEAREA 0.014 ;
		ANTENNADIFFAREA 0.018 ;
		ANTENNAPARTIALMETALAREA 0.025 ;
	END emaw[1]

	PIN q[0]
		USE SIGNAL ;
		DIRECTION OUTPUT ;
		SHAPE ABUTMENT ;
		PORT
			LAYER	M1 ;
			RECT	0 1.995 0.25 2.095 ;
			LAYER	M2 ;
			RECT	0 1.995 0.25 2.095 ;
			LAYER	M3 ;
			RECT	0 1.995 0.25 2.095 ;
		END

		ANTENNADIFFAREA 0.018 ;
		ANTENNAPARTIALMETALAREA 0.025 ;
	END q[0]

	PIN q[10]
		USE SIGNAL ;
		DIRECTION OUTPUT ;
		SHAPE ABUTMENT ;
		PORT
			LAYER	M1 ;
			RECT	0 16.195 0.25 16.295 ;
			LAYER	M2 ;
			RECT	0 16.195 0.25 16.295 ;
			LAYER	M3 ;
			RECT	0 16.195 0.25 16.295 ;
		END

		ANTENNADIFFAREA 0.018 ;
		ANTENNAPARTIALMETALAREA 0.025 ;
	END q[10]

	PIN q[11]
		USE SIGNAL ;
		DIRECTION OUTPUT ;
		SHAPE ABUTMENT ;
		PORT
			LAYER	M1 ;
			RECT	0 16.725 0.25 16.825 ;
			LAYER	M2 ;
			RECT	0 16.725 0.25 16.825 ;
			LAYER	M3 ;
			RECT	0 16.725 0.25 16.825 ;
		END

		ANTENNADIFFAREA 0.018 ;
		ANTENNAPARTIALMETALAREA 0.025 ;
	END q[11]

	PIN q[12]
		USE SIGNAL ;
		DIRECTION OUTPUT ;
		SHAPE ABUTMENT ;
		PORT
			LAYER	M1 ;
			RECT	0 19.035 0.25 19.135 ;
			LAYER	M2 ;
			RECT	0 19.035 0.25 19.135 ;
			LAYER	M3 ;
			RECT	0 19.035 0.25 19.135 ;
		END

		ANTENNADIFFAREA 0.018 ;
		ANTENNAPARTIALMETALAREA 0.025 ;
	END q[12]

	PIN q[13]
		USE SIGNAL ;
		DIRECTION OUTPUT ;
		SHAPE ABUTMENT ;
		PORT
			LAYER	M1 ;
			RECT	0 19.565 0.25 19.665 ;
			LAYER	M2 ;
			RECT	0 19.565 0.25 19.665 ;
			LAYER	M3 ;
			RECT	0 19.565 0.25 19.665 ;
		END

		ANTENNADIFFAREA 0.018 ;
		ANTENNAPARTIALMETALAREA 0.025 ;
	END q[13]

	PIN q[14]
		USE SIGNAL ;
		DIRECTION OUTPUT ;
		SHAPE ABUTMENT ;
		PORT
			LAYER	M1 ;
			RECT	0 21.875 0.25 21.975 ;
			LAYER	M2 ;
			RECT	0 21.875 0.25 21.975 ;
			LAYER	M3 ;
			RECT	0 21.875 0.25 21.975 ;
		END

		ANTENNADIFFAREA 0.018 ;
		ANTENNAPARTIALMETALAREA 0.025 ;
	END q[14]

	PIN q[15]
		USE SIGNAL ;
		DIRECTION OUTPUT ;
		SHAPE ABUTMENT ;
		PORT
			LAYER	M1 ;
			RECT	0 22.405 0.25 22.505 ;
			LAYER	M2 ;
			RECT	0 22.405 0.25 22.505 ;
			LAYER	M3 ;
			RECT	0 22.405 0.25 22.505 ;
		END

		ANTENNADIFFAREA 0.018 ;
		ANTENNAPARTIALMETALAREA 0.025 ;
	END q[15]

	PIN q[16]
		USE SIGNAL ;
		DIRECTION OUTPUT ;
		SHAPE ABUTMENT ;
		PORT
			LAYER	M1 ;
			RECT	0 24.715 0.25 24.815 ;
			LAYER	M2 ;
			RECT	0 24.715 0.25 24.815 ;
			LAYER	M3 ;
			RECT	0 24.715 0.25 24.815 ;
		END

		ANTENNADIFFAREA 0.018 ;
		ANTENNAPARTIALMETALAREA 0.025 ;
	END q[16]

	PIN q[17]
		USE SIGNAL ;
		DIRECTION OUTPUT ;
		SHAPE ABUTMENT ;
		PORT
			LAYER	M1 ;
			RECT	0 25.245 0.25 25.345 ;
			LAYER	M2 ;
			RECT	0 25.245 0.25 25.345 ;
			LAYER	M3 ;
			RECT	0 25.245 0.25 25.345 ;
		END

		ANTENNADIFFAREA 0.018 ;
		ANTENNAPARTIALMETALAREA 0.025 ;
	END q[17]

	PIN q[18]
		USE SIGNAL ;
		DIRECTION OUTPUT ;
		SHAPE ABUTMENT ;
		PORT
			LAYER	M1 ;
			RECT	0 27.555 0.25 27.655 ;
			LAYER	M2 ;
			RECT	0 27.555 0.25 27.655 ;
			LAYER	M3 ;
			RECT	0 27.555 0.25 27.655 ;
		END

		ANTENNADIFFAREA 0.018 ;
		ANTENNAPARTIALMETALAREA 0.025 ;
	END q[18]

	PIN q[19]
		USE SIGNAL ;
		DIRECTION OUTPUT ;
		SHAPE ABUTMENT ;
		PORT
			LAYER	M1 ;
			RECT	0 28.085 0.25 28.185 ;
			LAYER	M2 ;
			RECT	0 28.085 0.25 28.185 ;
			LAYER	M3 ;
			RECT	0 28.085 0.25 28.185 ;
		END

		ANTENNADIFFAREA 0.018 ;
		ANTENNAPARTIALMETALAREA 0.025 ;
	END q[19]

	PIN q[1]
		USE SIGNAL ;
		DIRECTION OUTPUT ;
		SHAPE ABUTMENT ;
		PORT
			LAYER	M1 ;
			RECT	0 2.525 0.25 2.625 ;
			LAYER	M2 ;
			RECT	0 2.525 0.25 2.625 ;
			LAYER	M3 ;
			RECT	0 2.525 0.25 2.625 ;
		END

		ANTENNADIFFAREA 0.018 ;
		ANTENNAPARTIALMETALAREA 0.025 ;
	END q[1]

	PIN q[20]
		USE SIGNAL ;
		DIRECTION OUTPUT ;
		SHAPE ABUTMENT ;
		PORT
			LAYER	M1 ;
			RECT	0 30.395 0.25 30.495 ;
			LAYER	M2 ;
			RECT	0 30.395 0.25 30.495 ;
			LAYER	M3 ;
			RECT	0 30.395 0.25 30.495 ;
		END

		ANTENNADIFFAREA 0.018 ;
		ANTENNAPARTIALMETALAREA 0.025 ;
	END q[20]

	PIN q[21]
		USE SIGNAL ;
		DIRECTION OUTPUT ;
		SHAPE ABUTMENT ;
		PORT
			LAYER	M1 ;
			RECT	0 30.925 0.25 31.025 ;
			LAYER	M2 ;
			RECT	0 30.925 0.25 31.025 ;
			LAYER	M3 ;
			RECT	0 30.925 0.25 31.025 ;
		END

		ANTENNADIFFAREA 0.018 ;
		ANTENNAPARTIALMETALAREA 0.025 ;
	END q[21]

	PIN q[22]
		USE SIGNAL ;
		DIRECTION OUTPUT ;
		SHAPE ABUTMENT ;
		PORT
			LAYER	M1 ;
			RECT	0 55.72 0.25 55.82 ;
			LAYER	M2 ;
			RECT	0 55.72 0.25 55.82 ;
			LAYER	M3 ;
			RECT	0 55.72 0.25 55.82 ;
		END

		ANTENNADIFFAREA 0.018 ;
		ANTENNAPARTIALMETALAREA 0.025 ;
	END q[22]

	PIN q[23]
		USE SIGNAL ;
		DIRECTION OUTPUT ;
		SHAPE ABUTMENT ;
		PORT
			LAYER	M1 ;
			RECT	0 56.25 0.25 56.35 ;
			LAYER	M2 ;
			RECT	0 56.25 0.25 56.35 ;
			LAYER	M3 ;
			RECT	0 56.25 0.25 56.35 ;
		END

		ANTENNADIFFAREA 0.018 ;
		ANTENNAPARTIALMETALAREA 0.025 ;
	END q[23]

	PIN q[24]
		USE SIGNAL ;
		DIRECTION OUTPUT ;
		SHAPE ABUTMENT ;
		PORT
			LAYER	M1 ;
			RECT	0 58.56 0.25 58.66 ;
			LAYER	M2 ;
			RECT	0 58.56 0.25 58.66 ;
			LAYER	M3 ;
			RECT	0 58.56 0.25 58.66 ;
		END

		ANTENNADIFFAREA 0.018 ;
		ANTENNAPARTIALMETALAREA 0.025 ;
	END q[24]

	PIN q[25]
		USE SIGNAL ;
		DIRECTION OUTPUT ;
		SHAPE ABUTMENT ;
		PORT
			LAYER	M1 ;
			RECT	0 59.09 0.25 59.19 ;
			LAYER	M2 ;
			RECT	0 59.09 0.25 59.19 ;
			LAYER	M3 ;
			RECT	0 59.09 0.25 59.19 ;
		END

		ANTENNADIFFAREA 0.018 ;
		ANTENNAPARTIALMETALAREA 0.025 ;
	END q[25]

	PIN q[26]
		USE SIGNAL ;
		DIRECTION OUTPUT ;
		SHAPE ABUTMENT ;
		PORT
			LAYER	M1 ;
			RECT	0 61.4 0.25 61.5 ;
			LAYER	M2 ;
			RECT	0 61.4 0.25 61.5 ;
			LAYER	M3 ;
			RECT	0 61.4 0.25 61.5 ;
		END

		ANTENNADIFFAREA 0.018 ;
		ANTENNAPARTIALMETALAREA 0.025 ;
	END q[26]

	PIN q[27]
		USE SIGNAL ;
		DIRECTION OUTPUT ;
		SHAPE ABUTMENT ;
		PORT
			LAYER	M1 ;
			RECT	0 61.93 0.25 62.03 ;
			LAYER	M2 ;
			RECT	0 61.93 0.25 62.03 ;
			LAYER	M3 ;
			RECT	0 61.93 0.25 62.03 ;
		END

		ANTENNADIFFAREA 0.018 ;
		ANTENNAPARTIALMETALAREA 0.025 ;
	END q[27]

	PIN q[28]
		USE SIGNAL ;
		DIRECTION OUTPUT ;
		SHAPE ABUTMENT ;
		PORT
			LAYER	M1 ;
			RECT	0 64.24 0.25 64.34 ;
			LAYER	M2 ;
			RECT	0 64.24 0.25 64.34 ;
			LAYER	M3 ;
			RECT	0 64.24 0.25 64.34 ;
		END

		ANTENNADIFFAREA 0.018 ;
		ANTENNAPARTIALMETALAREA 0.025 ;
	END q[28]

	PIN q[29]
		USE SIGNAL ;
		DIRECTION OUTPUT ;
		SHAPE ABUTMENT ;
		PORT
			LAYER	M1 ;
			RECT	0 64.77 0.25 64.87 ;
			LAYER	M2 ;
			RECT	0 64.77 0.25 64.87 ;
			LAYER	M3 ;
			RECT	0 64.77 0.25 64.87 ;
		END

		ANTENNADIFFAREA 0.018 ;
		ANTENNAPARTIALMETALAREA 0.025 ;
	END q[29]

	PIN q[2]
		USE SIGNAL ;
		DIRECTION OUTPUT ;
		SHAPE ABUTMENT ;
		PORT
			LAYER	M1 ;
			RECT	0 4.835 0.25 4.935 ;
			LAYER	M2 ;
			RECT	0 4.835 0.25 4.935 ;
			LAYER	M3 ;
			RECT	0 4.835 0.25 4.935 ;
		END

		ANTENNADIFFAREA 0.018 ;
		ANTENNAPARTIALMETALAREA 0.025 ;
	END q[2]

	PIN q[30]
		USE SIGNAL ;
		DIRECTION OUTPUT ;
		SHAPE ABUTMENT ;
		PORT
			LAYER	M1 ;
			RECT	0 67.08 0.25 67.18 ;
			LAYER	M2 ;
			RECT	0 67.08 0.25 67.18 ;
			LAYER	M3 ;
			RECT	0 67.08 0.25 67.18 ;
		END

		ANTENNADIFFAREA 0.018 ;
		ANTENNAPARTIALMETALAREA 0.025 ;
	END q[30]

	PIN q[31]
		USE SIGNAL ;
		DIRECTION OUTPUT ;
		SHAPE ABUTMENT ;
		PORT
			LAYER	M1 ;
			RECT	0 67.61 0.25 67.71 ;
			LAYER	M2 ;
			RECT	0 67.61 0.25 67.71 ;
			LAYER	M3 ;
			RECT	0 67.61 0.25 67.71 ;
		END

		ANTENNADIFFAREA 0.018 ;
		ANTENNAPARTIALMETALAREA 0.025 ;
	END q[31]

	PIN q[32]
		USE SIGNAL ;
		DIRECTION OUTPUT ;
		SHAPE ABUTMENT ;
		PORT
			LAYER	M1 ;
			RECT	0 69.92 0.25 70.02 ;
			LAYER	M2 ;
			RECT	0 69.92 0.25 70.02 ;
			LAYER	M3 ;
			RECT	0 69.92 0.25 70.02 ;
		END

		ANTENNADIFFAREA 0.018 ;
		ANTENNAPARTIALMETALAREA 0.025 ;
	END q[32]

	PIN q[33]
		USE SIGNAL ;
		DIRECTION OUTPUT ;
		SHAPE ABUTMENT ;
		PORT
			LAYER	M1 ;
			RECT	0 70.45 0.25 70.55 ;
			LAYER	M2 ;
			RECT	0 70.45 0.25 70.55 ;
			LAYER	M3 ;
			RECT	0 70.45 0.25 70.55 ;
		END

		ANTENNADIFFAREA 0.018 ;
		ANTENNAPARTIALMETALAREA 0.025 ;
	END q[33]

	PIN q[34]
		USE SIGNAL ;
		DIRECTION OUTPUT ;
		SHAPE ABUTMENT ;
		PORT
			LAYER	M1 ;
			RECT	0 72.76 0.25 72.86 ;
			LAYER	M2 ;
			RECT	0 72.76 0.25 72.86 ;
			LAYER	M3 ;
			RECT	0 72.76 0.25 72.86 ;
		END

		ANTENNADIFFAREA 0.018 ;
		ANTENNAPARTIALMETALAREA 0.025 ;
	END q[34]

	PIN q[35]
		USE SIGNAL ;
		DIRECTION OUTPUT ;
		SHAPE ABUTMENT ;
		PORT
			LAYER	M1 ;
			RECT	0 73.29 0.25 73.39 ;
			LAYER	M2 ;
			RECT	0 73.29 0.25 73.39 ;
			LAYER	M3 ;
			RECT	0 73.29 0.25 73.39 ;
		END

		ANTENNADIFFAREA 0.018 ;
		ANTENNAPARTIALMETALAREA 0.025 ;
	END q[35]

	PIN q[36]
		USE SIGNAL ;
		DIRECTION OUTPUT ;
		SHAPE ABUTMENT ;
		PORT
			LAYER	M1 ;
			RECT	0 75.6 0.25 75.7 ;
			LAYER	M2 ;
			RECT	0 75.6 0.25 75.7 ;
			LAYER	M3 ;
			RECT	0 75.6 0.25 75.7 ;
		END

		ANTENNADIFFAREA 0.018 ;
		ANTENNAPARTIALMETALAREA 0.025 ;
	END q[36]

	PIN q[37]
		USE SIGNAL ;
		DIRECTION OUTPUT ;
		SHAPE ABUTMENT ;
		PORT
			LAYER	M1 ;
			RECT	0 76.13 0.25 76.23 ;
			LAYER	M2 ;
			RECT	0 76.13 0.25 76.23 ;
			LAYER	M3 ;
			RECT	0 76.13 0.25 76.23 ;
		END

		ANTENNADIFFAREA 0.018 ;
		ANTENNAPARTIALMETALAREA 0.025 ;
	END q[37]

	PIN q[38]
		USE SIGNAL ;
		DIRECTION OUTPUT ;
		SHAPE ABUTMENT ;
		PORT
			LAYER	M1 ;
			RECT	0 78.44 0.25 78.54 ;
			LAYER	M2 ;
			RECT	0 78.44 0.25 78.54 ;
			LAYER	M3 ;
			RECT	0 78.44 0.25 78.54 ;
		END

		ANTENNADIFFAREA 0.018 ;
		ANTENNAPARTIALMETALAREA 0.025 ;
	END q[38]

	PIN q[39]
		USE SIGNAL ;
		DIRECTION OUTPUT ;
		SHAPE ABUTMENT ;
		PORT
			LAYER	M1 ;
			RECT	0 78.97 0.25 79.07 ;
			LAYER	M2 ;
			RECT	0 78.97 0.25 79.07 ;
			LAYER	M3 ;
			RECT	0 78.97 0.25 79.07 ;
		END

		ANTENNADIFFAREA 0.018 ;
		ANTENNAPARTIALMETALAREA 0.025 ;
	END q[39]

	PIN q[3]
		USE SIGNAL ;
		DIRECTION OUTPUT ;
		SHAPE ABUTMENT ;
		PORT
			LAYER	M1 ;
			RECT	0 5.365 0.25 5.465 ;
			LAYER	M2 ;
			RECT	0 5.365 0.25 5.465 ;
			LAYER	M3 ;
			RECT	0 5.365 0.25 5.465 ;
		END

		ANTENNADIFFAREA 0.018 ;
		ANTENNAPARTIALMETALAREA 0.025 ;
	END q[3]

	PIN q[40]
		USE SIGNAL ;
		DIRECTION OUTPUT ;
		SHAPE ABUTMENT ;
		PORT
			LAYER	M1 ;
			RECT	0 81.28 0.25 81.38 ;
			LAYER	M2 ;
			RECT	0 81.28 0.25 81.38 ;
			LAYER	M3 ;
			RECT	0 81.28 0.25 81.38 ;
		END

		ANTENNADIFFAREA 0.018 ;
		ANTENNAPARTIALMETALAREA 0.025 ;
	END q[40]

	PIN q[41]
		USE SIGNAL ;
		DIRECTION OUTPUT ;
		SHAPE ABUTMENT ;
		PORT
			LAYER	M1 ;
			RECT	0 81.81 0.25 81.91 ;
			LAYER	M2 ;
			RECT	0 81.81 0.25 81.91 ;
			LAYER	M3 ;
			RECT	0 81.81 0.25 81.91 ;
		END

		ANTENNADIFFAREA 0.018 ;
		ANTENNAPARTIALMETALAREA 0.025 ;
	END q[41]

	PIN q[42]
		USE SIGNAL ;
		DIRECTION OUTPUT ;
		SHAPE ABUTMENT ;
		PORT
			LAYER	M1 ;
			RECT	0 84.12 0.25 84.22 ;
			LAYER	M2 ;
			RECT	0 84.12 0.25 84.22 ;
			LAYER	M3 ;
			RECT	0 84.12 0.25 84.22 ;
		END

		ANTENNADIFFAREA 0.018 ;
		ANTENNAPARTIALMETALAREA 0.025 ;
	END q[42]

	PIN q[43]
		USE SIGNAL ;
		DIRECTION OUTPUT ;
		SHAPE ABUTMENT ;
		PORT
			LAYER	M1 ;
			RECT	0 84.65 0.25 84.75 ;
			LAYER	M2 ;
			RECT	0 84.65 0.25 84.75 ;
			LAYER	M3 ;
			RECT	0 84.65 0.25 84.75 ;
		END

		ANTENNADIFFAREA 0.018 ;
		ANTENNAPARTIALMETALAREA 0.025 ;
	END q[43]

	PIN q[44]
		USE SIGNAL ;
		DIRECTION OUTPUT ;
		SHAPE ABUTMENT ;
		PORT
			LAYER	M1 ;
			RECT	0 86.96 0.25 87.06 ;
			LAYER	M2 ;
			RECT	0 86.96 0.25 87.06 ;
			LAYER	M3 ;
			RECT	0 86.96 0.25 87.06 ;
		END

		ANTENNADIFFAREA 0.018 ;
		ANTENNAPARTIALMETALAREA 0.025 ;
	END q[44]

	PIN q[45]
		USE SIGNAL ;
		DIRECTION OUTPUT ;
		SHAPE ABUTMENT ;
		PORT
			LAYER	M1 ;
			RECT	0 87.49 0.25 87.59 ;
			LAYER	M2 ;
			RECT	0 87.49 0.25 87.59 ;
			LAYER	M3 ;
			RECT	0 87.49 0.25 87.59 ;
		END

		ANTENNADIFFAREA 0.018 ;
		ANTENNAPARTIALMETALAREA 0.025 ;
	END q[45]

	PIN q[4]
		USE SIGNAL ;
		DIRECTION OUTPUT ;
		SHAPE ABUTMENT ;
		PORT
			LAYER	M1 ;
			RECT	0 7.675 0.25 7.775 ;
			LAYER	M2 ;
			RECT	0 7.675 0.25 7.775 ;
			LAYER	M3 ;
			RECT	0 7.675 0.25 7.775 ;
		END

		ANTENNADIFFAREA 0.018 ;
		ANTENNAPARTIALMETALAREA 0.025 ;
	END q[4]

	PIN q[5]
		USE SIGNAL ;
		DIRECTION OUTPUT ;
		SHAPE ABUTMENT ;
		PORT
			LAYER	M1 ;
			RECT	0 8.205 0.25 8.305 ;
			LAYER	M2 ;
			RECT	0 8.205 0.25 8.305 ;
			LAYER	M3 ;
			RECT	0 8.205 0.25 8.305 ;
		END

		ANTENNADIFFAREA 0.018 ;
		ANTENNAPARTIALMETALAREA 0.025 ;
	END q[5]

	PIN q[6]
		USE SIGNAL ;
		DIRECTION OUTPUT ;
		SHAPE ABUTMENT ;
		PORT
			LAYER	M1 ;
			RECT	0 10.515 0.25 10.615 ;
			LAYER	M2 ;
			RECT	0 10.515 0.25 10.615 ;
			LAYER	M3 ;
			RECT	0 10.515 0.25 10.615 ;
		END

		ANTENNADIFFAREA 0.018 ;
		ANTENNAPARTIALMETALAREA 0.025 ;
	END q[6]

	PIN q[7]
		USE SIGNAL ;
		DIRECTION OUTPUT ;
		SHAPE ABUTMENT ;
		PORT
			LAYER	M1 ;
			RECT	0 11.045 0.25 11.145 ;
			LAYER	M2 ;
			RECT	0 11.045 0.25 11.145 ;
			LAYER	M3 ;
			RECT	0 11.045 0.25 11.145 ;
		END

		ANTENNADIFFAREA 0.018 ;
		ANTENNAPARTIALMETALAREA 0.025 ;
	END q[7]

	PIN q[8]
		USE SIGNAL ;
		DIRECTION OUTPUT ;
		SHAPE ABUTMENT ;
		PORT
			LAYER	M1 ;
			RECT	0 13.355 0.25 13.455 ;
			LAYER	M2 ;
			RECT	0 13.355 0.25 13.455 ;
			LAYER	M3 ;
			RECT	0 13.355 0.25 13.455 ;
		END

		ANTENNADIFFAREA 0.018 ;
		ANTENNAPARTIALMETALAREA 0.025 ;
	END q[8]

	PIN q[9]
		USE SIGNAL ;
		DIRECTION OUTPUT ;
		SHAPE ABUTMENT ;
		PORT
			LAYER	M1 ;
			RECT	0 13.885 0.25 13.985 ;
			LAYER	M2 ;
			RECT	0 13.885 0.25 13.985 ;
			LAYER	M3 ;
			RECT	0 13.885 0.25 13.985 ;
		END

		ANTENNADIFFAREA 0.018 ;
		ANTENNAPARTIALMETALAREA 0.025 ;
	END q[9]

	PIN rawl
		USE SIGNAL ;
		DIRECTION INPUT ;
		SHAPE ABUTMENT ;
		PORT
			LAYER	M1 ;
			RECT	0 38.88 0.25 38.98 ;
			LAYER	M2 ;
			RECT	0 38.88 0.25 38.98 ;
			LAYER	M3 ;
			RECT	0 38.88 0.25 38.98 ;
		END

		ANTENNAGATEAREA 0.014 ;
		ANTENNADIFFAREA 0.018 ;
		ANTENNAPARTIALMETALAREA 0.025 ;
	END rawl

	PIN rawlm[0]
		USE SIGNAL ;
		DIRECTION INPUT ;
		SHAPE ABUTMENT ;
		PORT
			LAYER	M1 ;
			RECT	0 39.18 0.25 39.28 ;
			LAYER	M2 ;
			RECT	0 39.18 0.25 39.28 ;
			LAYER	M3 ;
			RECT	0 39.18 0.25 39.28 ;
		END

		ANTENNAGATEAREA 0.014 ;
		ANTENNADIFFAREA 0.018 ;
		ANTENNAPARTIALMETALAREA 0.025 ;
	END rawlm[0]

	PIN rawlm[1]
		USE SIGNAL ;
		DIRECTION INPUT ;
		SHAPE ABUTMENT ;
		PORT
			LAYER	M1 ;
			RECT	0 39.43 0.25 39.53 ;
			LAYER	M2 ;
			RECT	0 39.43 0.25 39.53 ;
			LAYER	M3 ;
			RECT	0 39.43 0.25 39.53 ;
		END

		ANTENNAGATEAREA 0.014 ;
		ANTENNADIFFAREA 0.018 ;
		ANTENNAPARTIALMETALAREA 0.025 ;
	END rawlm[1]

	PIN ret1n
		USE SIGNAL ;
		DIRECTION INPUT ;
		SHAPE ABUTMENT ;
		PORT
			LAYER	M1 ;
			RECT	0 34.425 0.25 34.525 ;
			LAYER	M2 ;
			RECT	0 34.425 0.25 34.525 ;
			LAYER	M3 ;
			RECT	0 34.425 0.25 34.525 ;
		END

		ANTENNAGATEAREA 0.014 ;
		ANTENNADIFFAREA 0.018 ;
		ANTENNAPARTIALMETALAREA 0.025 ;
	END ret1n

	PIN wabl
		USE SIGNAL ;
		DIRECTION INPUT ;
		SHAPE ABUTMENT ;
		PORT
			LAYER	M1 ;
			RECT	0 53.34 0.25 53.44 ;
			LAYER	M2 ;
			RECT	0 53.34 0.25 53.44 ;
			LAYER	M3 ;
			RECT	0 53.34 0.25 53.44 ;
		END

		ANTENNAGATEAREA 0.014 ;
		ANTENNADIFFAREA 0.018 ;
		ANTENNAPARTIALMETALAREA 0.025 ;
	END wabl

	PIN wablm[0]
		USE SIGNAL ;
		DIRECTION INPUT ;
		SHAPE ABUTMENT ;
		PORT
			LAYER	M1 ;
			RECT	0 49.825 0.25 49.925 ;
			LAYER	M2 ;
			RECT	0 49.825 0.25 49.925 ;
			LAYER	M3 ;
			RECT	0 49.825 0.25 49.925 ;
		END

		ANTENNAGATEAREA 0.014 ;
		ANTENNADIFFAREA 0.018 ;
		ANTENNAPARTIALMETALAREA 0.025 ;
	END wablm[0]

	PIN wablm[1]
		USE SIGNAL ;
		DIRECTION INPUT ;
		SHAPE ABUTMENT ;
		PORT
			LAYER	M1 ;
			RECT	0 44.855 0.25 44.955 ;
			LAYER	M2 ;
			RECT	0 44.855 0.25 44.955 ;
			LAYER	M3 ;
			RECT	0 44.855 0.25 44.955 ;
		END

		ANTENNAGATEAREA 0.014 ;
		ANTENNADIFFAREA 0.018 ;
		ANTENNAPARTIALMETALAREA 0.025 ;
	END wablm[1]

	PIN wen
		USE SIGNAL ;
		DIRECTION INPUT ;
		SHAPE ABUTMENT ;
		PORT
			LAYER	M1 ;
			RECT	0 38.385 0.25 38.485 ;
			LAYER	M2 ;
			RECT	0 38.385 0.25 38.485 ;
			LAYER	M3 ;
			RECT	0 38.385 0.25 38.485 ;
		END

		ANTENNAGATEAREA 0.014 ;
		ANTENNADIFFAREA 0.018 ;
		ANTENNAPARTIALMETALAREA 0.025 ;
	END wen

	OBS
		LAYER	M1 DESIGNRULEWIDTH 0.165 ;
		RECT	0.32 0.3 38.08 89.285 ;
		RECT	0 0 0.32 1.315 ;
		RECT	0 1.515 0.32 1.945 ;
		RECT	0 2.145 0.32 2.475 ;
		RECT	0 2.675 0.32 3.105 ;
		RECT	0 3.305 0.32 4.155 ;
		RECT	0 4.355 0.32 4.785 ;
		RECT	0 4.985 0.32 5.315 ;
		RECT	0 5.515 0.32 5.945 ;
		RECT	0 6.145 0.32 6.995 ;
		RECT	0 7.195 0.32 7.625 ;
		RECT	0 7.825 0.32 8.155 ;
		RECT	0 8.355 0.32 8.785 ;
		RECT	0 8.985 0.32 9.835 ;
		RECT	0 10.035 0.32 10.465 ;
		RECT	0 10.665 0.32 10.995 ;
		RECT	0 11.195 0.32 11.625 ;
		RECT	0 11.825 0.32 12.675 ;
		RECT	0 12.875 0.32 13.305 ;
		RECT	0 13.505 0.32 13.835 ;
		RECT	0 14.035 0.32 14.465 ;
		RECT	0 14.665 0.32 15.515 ;
		RECT	0 15.715 0.32 16.145 ;
		RECT	0 16.345 0.32 16.675 ;
		RECT	0 16.875 0.32 17.305 ;
		RECT	0 17.505 0.32 18.355 ;
		RECT	0 18.555 0.32 18.985 ;
		RECT	0 19.185 0.32 19.515 ;
		RECT	0 19.715 0.32 20.145 ;
		RECT	0 20.345 0.32 21.195 ;
		RECT	0 21.395 0.32 21.825 ;
		RECT	0 22.025 0.32 22.355 ;
		RECT	0 22.555 0.32 22.985 ;
		RECT	0 23.185 0.32 24.035 ;
		RECT	0 24.235 0.32 24.665 ;
		RECT	0 24.865 0.32 25.195 ;
		RECT	0 25.395 0.32 25.825 ;
		RECT	0 26.025 0.32 26.875 ;
		RECT	0 27.075 0.32 27.505 ;
		RECT	0 27.705 0.32 28.035 ;
		RECT	0 28.235 0.32 28.665 ;
		RECT	0 28.865 0.32 29.715 ;
		RECT	0 29.915 0.32 30.345 ;
		RECT	0 30.545 0.32 30.875 ;
		RECT	0 31.075 0.32 31.505 ;
		RECT	0 31.705 0.32 34.375 ;
		RECT	0 34.575 0.32 36.82 ;
		RECT	0 37.02 0.32 37.21 ;
		RECT	0 37.41 0.32 38.335 ;
		RECT	0 38.535 0.32 38.83 ;
		RECT	0 39.03 0.32 39.13 ;
		RECT	0 39.33 0.32 39.38 ;
		RECT	0 39.58 0.32 40.2 ;
		RECT	0 40.4 0.32 40.8 ;
		RECT	0 41 0.32 41.2 ;
		RECT	0 41.4 0.32 43.11 ;
		RECT	0 43.31 0.32 43.44 ;
		RECT	0 43.64 0.32 44.805 ;
		RECT	0 45.005 0.32 45.545 ;
		RECT	0 45.745 0.32 46.015 ;
		RECT	0 46.615 0.32 46.815 ;
		RECT	0 47.015 0.32 49.775 ;
		RECT	0 49.975 0.32 52.695 ;
		RECT	0 52.895 0.32 53.07 ;
		RECT	0 53.49 0.32 55.04 ;
		RECT	0 55.24 0.32 55.67 ;
		RECT	0 55.87 0.32 56.2 ;
		RECT	0 56.4 0.32 56.83 ;
		RECT	0 57.03 0.32 57.88 ;
		RECT	0 58.08 0.32 58.51 ;
		RECT	0 58.71 0.32 59.04 ;
		RECT	0 59.24 0.32 59.67 ;
		RECT	0 59.87 0.32 60.72 ;
		RECT	0 60.92 0.32 61.35 ;
		RECT	0 61.55 0.32 61.88 ;
		RECT	0 62.08 0.32 62.51 ;
		RECT	0 62.71 0.32 63.56 ;
		RECT	0 63.76 0.32 64.19 ;
		RECT	0 64.39 0.32 64.72 ;
		RECT	0 64.92 0.32 65.35 ;
		RECT	0 65.55 0.32 66.4 ;
		RECT	0 66.6 0.32 67.03 ;
		RECT	0 67.23 0.32 67.56 ;
		RECT	0 67.76 0.32 68.19 ;
		RECT	0 68.39 0.32 69.24 ;
		RECT	0 69.44 0.32 69.87 ;
		RECT	0 70.07 0.32 70.4 ;
		RECT	0 70.6 0.32 71.03 ;
		RECT	0 71.23 0.32 72.08 ;
		RECT	0 72.28 0.32 72.71 ;
		RECT	0 72.91 0.32 73.24 ;
		RECT	0 73.44 0.32 73.87 ;
		RECT	0 74.07 0.32 74.92 ;
		RECT	0 75.12 0.32 75.55 ;
		RECT	0 75.75 0.32 76.08 ;
		RECT	0 76.28 0.32 76.71 ;
		RECT	0 76.91 0.32 77.76 ;
		RECT	0 77.96 0.32 78.39 ;
		RECT	0 78.59 0.32 78.92 ;
		RECT	0 79.12 0.32 79.55 ;
		RECT	0 79.75 0.32 80.6 ;
		RECT	0 80.8 0.32 81.23 ;
		RECT	0 81.43 0.32 81.76 ;
		RECT	0 81.96 0.32 82.39 ;
		RECT	0 82.59 0.32 83.44 ;
		RECT	0 83.64 0.32 84.07 ;
		RECT	0 84.27 0.32 84.6 ;
		RECT	0 84.8 0.32 85.23 ;
		RECT	0 85.43 0.32 86.28 ;
		RECT	0 86.48 0.32 86.91 ;
		RECT	0 87.11 0.32 87.44 ;
		RECT	0 87.64 0.32 88.07 ;
		RECT	0 88.27 0.32 89.585 ;
		RECT	38.08 0 38.4 89.585 ;
		RECT	0.32 0 38.08 0.3 ;
		RECT	0.32 89.285 38.08 89.585 ;
		LAYER	M2 DESIGNRULEWIDTH 0.165 ;
		RECT	0.32 0.3 38.08 89.285 ;
		RECT	0 0 0.32 1.315 ;
		RECT	0 1.515 0.32 1.945 ;
		RECT	0 2.145 0.32 2.475 ;
		RECT	0 2.675 0.32 3.105 ;
		RECT	0 3.305 0.32 4.155 ;
		RECT	0 4.355 0.32 4.785 ;
		RECT	0 4.985 0.32 5.315 ;
		RECT	0 5.515 0.32 5.945 ;
		RECT	0 6.145 0.32 6.995 ;
		RECT	0 7.195 0.32 7.625 ;
		RECT	0 7.825 0.32 8.155 ;
		RECT	0 8.355 0.32 8.785 ;
		RECT	0 8.985 0.32 9.835 ;
		RECT	0 10.035 0.32 10.465 ;
		RECT	0 10.665 0.32 10.995 ;
		RECT	0 11.195 0.32 11.625 ;
		RECT	0 11.825 0.32 12.675 ;
		RECT	0 12.875 0.32 13.305 ;
		RECT	0 13.505 0.32 13.835 ;
		RECT	0 14.035 0.32 14.465 ;
		RECT	0 14.665 0.32 15.515 ;
		RECT	0 15.715 0.32 16.145 ;
		RECT	0 16.345 0.32 16.675 ;
		RECT	0 16.875 0.32 17.305 ;
		RECT	0 17.505 0.32 18.355 ;
		RECT	0 18.555 0.32 18.985 ;
		RECT	0 19.185 0.32 19.515 ;
		RECT	0 19.715 0.32 20.145 ;
		RECT	0 20.345 0.32 21.195 ;
		RECT	0 21.395 0.32 21.825 ;
		RECT	0 22.025 0.32 22.355 ;
		RECT	0 22.555 0.32 22.985 ;
		RECT	0 23.185 0.32 24.035 ;
		RECT	0 24.235 0.32 24.665 ;
		RECT	0 24.865 0.32 25.195 ;
		RECT	0 25.395 0.32 25.825 ;
		RECT	0 26.025 0.32 26.875 ;
		RECT	0 27.075 0.32 27.505 ;
		RECT	0 27.705 0.32 28.035 ;
		RECT	0 28.235 0.32 28.665 ;
		RECT	0 28.865 0.32 29.715 ;
		RECT	0 29.915 0.32 30.345 ;
		RECT	0 30.545 0.32 30.875 ;
		RECT	0 31.075 0.32 31.505 ;
		RECT	0 31.705 0.32 34.375 ;
		RECT	0 34.575 0.32 36.82 ;
		RECT	0 37.02 0.32 37.21 ;
		RECT	0 37.41 0.32 38.335 ;
		RECT	0 38.535 0.32 38.83 ;
		RECT	0 39.03 0.32 39.13 ;
		RECT	0 39.33 0.32 39.38 ;
		RECT	0 39.58 0.32 40.005 ;
		RECT	0 40.4 0.32 40.8 ;
		RECT	0 41 0.32 41.2 ;
		RECT	0 41.4 0.32 43.11 ;
		RECT	0 43.31 0.32 43.44 ;
		RECT	0 43.64 0.32 44.805 ;
		RECT	0 45.005 0.32 45.545 ;
		RECT	0 45.745 0.32 46.015 ;
		RECT	0 46.615 0.32 46.815 ;
		RECT	0 47.015 0.32 49.775 ;
		RECT	0 49.975 0.32 52.695 ;
		RECT	0 52.895 0.32 53.07 ;
		RECT	0 53.49 0.32 55.04 ;
		RECT	0 55.24 0.32 55.67 ;
		RECT	0 55.87 0.32 56.2 ;
		RECT	0 56.4 0.32 56.83 ;
		RECT	0 57.03 0.32 57.88 ;
		RECT	0 58.08 0.32 58.51 ;
		RECT	0 58.71 0.32 59.04 ;
		RECT	0 59.24 0.32 59.67 ;
		RECT	0 59.87 0.32 60.72 ;
		RECT	0 60.92 0.32 61.35 ;
		RECT	0 61.55 0.32 61.88 ;
		RECT	0 62.08 0.32 62.51 ;
		RECT	0 62.71 0.32 63.56 ;
		RECT	0 63.76 0.32 64.19 ;
		RECT	0 64.39 0.32 64.72 ;
		RECT	0 64.92 0.32 65.35 ;
		RECT	0 65.55 0.32 66.4 ;
		RECT	0 66.6 0.32 67.03 ;
		RECT	0 67.23 0.32 67.56 ;
		RECT	0 67.76 0.32 68.19 ;
		RECT	0 68.39 0.32 69.24 ;
		RECT	0 69.44 0.32 69.87 ;
		RECT	0 70.07 0.32 70.4 ;
		RECT	0 70.6 0.32 71.03 ;
		RECT	0 71.23 0.32 72.08 ;
		RECT	0 72.28 0.32 72.71 ;
		RECT	0 72.91 0.32 73.24 ;
		RECT	0 73.44 0.32 73.87 ;
		RECT	0 74.07 0.32 74.92 ;
		RECT	0 75.12 0.32 75.55 ;
		RECT	0 75.75 0.32 76.08 ;
		RECT	0 76.28 0.32 76.71 ;
		RECT	0 76.91 0.32 77.76 ;
		RECT	0 77.96 0.32 78.39 ;
		RECT	0 78.59 0.32 78.92 ;
		RECT	0 79.12 0.32 79.55 ;
		RECT	0 79.75 0.32 80.6 ;
		RECT	0 80.8 0.32 81.23 ;
		RECT	0 81.43 0.32 81.76 ;
		RECT	0 81.96 0.32 82.39 ;
		RECT	0 82.59 0.32 83.44 ;
		RECT	0 83.64 0.32 84.07 ;
		RECT	0 84.27 0.32 84.6 ;
		RECT	0 84.8 0.32 85.23 ;
		RECT	0 85.43 0.32 86.28 ;
		RECT	0 86.48 0.32 86.91 ;
		RECT	0 87.11 0.32 87.44 ;
		RECT	0 87.64 0.32 88.07 ;
		RECT	0 88.27 0.32 89.585 ;
		RECT	38.08 0 38.4 89.585 ;
		RECT	0.32 0 38.08 0.3 ;
		RECT	0.32 89.285 38.08 89.585 ;
		LAYER	M3 DESIGNRULEWIDTH 0.165 ;
		RECT	0.32 0.3 38.08 89.285 ;
		RECT	0 0 0.32 1.315 ;
		RECT	0 1.515 0.32 1.945 ;
		RECT	0 2.145 0.32 2.475 ;
		RECT	0 2.675 0.32 3.105 ;
		RECT	0 3.305 0.32 4.155 ;
		RECT	0 4.355 0.32 4.785 ;
		RECT	0 4.985 0.32 5.315 ;
		RECT	0 5.515 0.32 5.945 ;
		RECT	0 6.145 0.32 6.995 ;
		RECT	0 7.195 0.32 7.625 ;
		RECT	0 7.825 0.32 8.155 ;
		RECT	0 8.355 0.32 8.785 ;
		RECT	0 8.985 0.32 9.835 ;
		RECT	0 10.035 0.32 10.465 ;
		RECT	0 10.665 0.32 10.995 ;
		RECT	0 11.195 0.32 11.625 ;
		RECT	0 11.825 0.32 12.675 ;
		RECT	0 12.875 0.32 13.305 ;
		RECT	0 13.505 0.32 13.835 ;
		RECT	0 14.035 0.32 14.465 ;
		RECT	0 14.665 0.32 15.515 ;
		RECT	0 15.715 0.32 16.145 ;
		RECT	0 16.345 0.32 16.675 ;
		RECT	0 16.875 0.32 17.305 ;
		RECT	0 17.505 0.32 18.355 ;
		RECT	0 18.555 0.32 18.985 ;
		RECT	0 19.185 0.32 19.515 ;
		RECT	0 19.715 0.32 20.145 ;
		RECT	0 20.345 0.32 21.195 ;
		RECT	0 21.395 0.32 21.825 ;
		RECT	0 22.025 0.32 22.355 ;
		RECT	0 22.555 0.32 22.985 ;
		RECT	0 23.185 0.32 24.035 ;
		RECT	0 24.235 0.32 24.665 ;
		RECT	0 24.865 0.32 25.195 ;
		RECT	0 25.395 0.32 25.825 ;
		RECT	0 26.025 0.32 26.875 ;
		RECT	0 27.075 0.32 27.505 ;
		RECT	0 27.705 0.32 28.035 ;
		RECT	0 28.235 0.32 28.665 ;
		RECT	0 28.865 0.32 29.715 ;
		RECT	0 29.915 0.32 30.345 ;
		RECT	0 30.545 0.32 30.875 ;
		RECT	0 31.075 0.32 31.505 ;
		RECT	0 31.705 0.32 34.375 ;
		RECT	0 34.575 0.32 36.82 ;
		RECT	0 37.02 0.32 37.21 ;
		RECT	0 37.41 0.32 38.335 ;
		RECT	0 38.535 0.32 38.83 ;
		RECT	0 39.03 0.32 39.13 ;
		RECT	0 39.33 0.32 39.38 ;
		RECT	0 39.58 0.32 40.005 ;
		RECT	0 40.4 0.32 40.8 ;
		RECT	0 41 0.32 41.2 ;
		RECT	0 41.4 0.32 43.11 ;
		RECT	0 43.31 0.32 43.44 ;
		RECT	0 43.64 0.32 44.805 ;
		RECT	0 45.005 0.32 45.545 ;
		RECT	0 45.745 0.32 46.015 ;
		RECT	0 46.615 0.32 46.815 ;
		RECT	0 47.015 0.32 49.775 ;
		RECT	0 49.975 0.32 52.695 ;
		RECT	0 52.895 0.32 53.07 ;
		RECT	0 53.49 0.32 55.04 ;
		RECT	0 55.24 0.32 55.67 ;
		RECT	0 55.87 0.32 56.2 ;
		RECT	0 56.4 0.32 56.83 ;
		RECT	0 57.03 0.32 57.88 ;
		RECT	0 58.08 0.32 58.51 ;
		RECT	0 58.71 0.32 59.04 ;
		RECT	0 59.24 0.32 59.67 ;
		RECT	0 59.87 0.32 60.72 ;
		RECT	0 60.92 0.32 61.35 ;
		RECT	0 61.55 0.32 61.88 ;
		RECT	0 62.08 0.32 62.51 ;
		RECT	0 62.71 0.32 63.56 ;
		RECT	0 63.76 0.32 64.19 ;
		RECT	0 64.39 0.32 64.72 ;
		RECT	0 64.92 0.32 65.35 ;
		RECT	0 65.55 0.32 66.4 ;
		RECT	0 66.6 0.32 67.03 ;
		RECT	0 67.23 0.32 67.56 ;
		RECT	0 67.76 0.32 68.19 ;
		RECT	0 68.39 0.32 69.24 ;
		RECT	0 69.44 0.32 69.87 ;
		RECT	0 70.07 0.32 70.4 ;
		RECT	0 70.6 0.32 71.03 ;
		RECT	0 71.23 0.32 72.08 ;
		RECT	0 72.28 0.32 72.71 ;
		RECT	0 72.91 0.32 73.24 ;
		RECT	0 73.44 0.32 73.87 ;
		RECT	0 74.07 0.32 74.92 ;
		RECT	0 75.12 0.32 75.55 ;
		RECT	0 75.75 0.32 76.08 ;
		RECT	0 76.28 0.32 76.71 ;
		RECT	0 76.91 0.32 77.76 ;
		RECT	0 77.96 0.32 78.39 ;
		RECT	0 78.59 0.32 78.92 ;
		RECT	0 79.12 0.32 79.55 ;
		RECT	0 79.75 0.32 80.6 ;
		RECT	0 80.8 0.32 81.23 ;
		RECT	0 81.43 0.32 81.76 ;
		RECT	0 81.96 0.32 82.39 ;
		RECT	0 82.59 0.32 83.44 ;
		RECT	0 83.64 0.32 84.07 ;
		RECT	0 84.27 0.32 84.6 ;
		RECT	0 84.8 0.32 85.23 ;
		RECT	0 85.43 0.32 86.28 ;
		RECT	0 86.48 0.32 86.91 ;
		RECT	0 87.11 0.32 87.44 ;
		RECT	0 87.64 0.32 88.07 ;
		RECT	0 88.27 0.32 89.585 ;
		RECT	38.08 0 38.4 89.585 ;
		RECT	0.32 0 38.08 0.3 ;
		RECT	0.32 89.285 38.08 89.585 ;
		LAYER	M4 DESIGNRULEWIDTH 0.165 ;
		RECT	0.32 0 38.08 0.09 ;
		RECT	0 0 0.32 0.09 ;
		RECT	38.08 0 38.4 0.09 ;
		RECT	0.32 0.9 38.08 1.99 ;
		RECT	0 0.9 0.32 1.99 ;
		RECT	38.08 0.9 38.4 1.99 ;
		RECT	0.32 2.76 38.08 2.83 ;
		RECT	0 2.76 0.32 2.83 ;
		RECT	38.08 2.76 38.4 2.83 ;
		RECT	0.32 3.63 38.08 4.83 ;
		RECT	0 3.63 0.32 4.83 ;
		RECT	38.08 3.63 38.4 4.83 ;
		RECT	0.32 5.6 38.08 5.67 ;
		RECT	0 5.6 0.32 5.67 ;
		RECT	38.08 5.6 38.4 5.67 ;
		RECT	0.32 6.47 38.08 7.67 ;
		RECT	0 6.47 0.32 7.67 ;
		RECT	38.08 6.47 38.4 7.67 ;
		RECT	0.32 8.44 38.08 8.51 ;
		RECT	0 8.44 0.32 8.51 ;
		RECT	38.08 8.44 38.4 8.51 ;
		RECT	0.32 9.31 38.08 10.51 ;
		RECT	0 9.31 0.32 10.51 ;
		RECT	38.08 9.31 38.4 10.51 ;
		RECT	0.32 11.28 38.08 11.35 ;
		RECT	0 11.28 0.32 11.35 ;
		RECT	38.08 11.28 38.4 11.35 ;
		RECT	0.32 12.15 38.08 13.35 ;
		RECT	0 12.15 0.32 13.35 ;
		RECT	38.08 12.15 38.4 13.35 ;
		RECT	0.32 14.12 38.08 14.19 ;
		RECT	0 14.12 0.32 14.19 ;
		RECT	38.08 14.12 38.4 14.19 ;
		RECT	0.32 14.99 38.08 16.19 ;
		RECT	0 14.99 0.32 16.19 ;
		RECT	38.08 14.99 38.4 16.19 ;
		RECT	0.32 16.96 38.08 17.03 ;
		RECT	0 16.96 0.32 17.03 ;
		RECT	38.08 16.96 38.4 17.03 ;
		RECT	0.32 17.83 38.08 19.03 ;
		RECT	0 17.83 0.32 19.03 ;
		RECT	38.08 17.83 38.4 19.03 ;
		RECT	0.32 19.8 38.08 19.87 ;
		RECT	0 19.8 0.32 19.87 ;
		RECT	38.08 19.8 38.4 19.87 ;
		RECT	0.32 20.67 38.08 21.87 ;
		RECT	0 20.67 0.32 21.87 ;
		RECT	38.08 20.67 38.4 21.87 ;
		RECT	0.32 22.64 38.08 22.71 ;
		RECT	0 22.64 0.32 22.71 ;
		RECT	38.08 22.64 38.4 22.71 ;
		RECT	0.32 23.51 38.08 24.71 ;
		RECT	0 23.51 0.32 24.71 ;
		RECT	38.08 23.51 38.4 24.71 ;
		RECT	0.32 25.48 38.08 25.55 ;
		RECT	0 25.48 0.32 25.55 ;
		RECT	38.08 25.48 38.4 25.55 ;
		RECT	0.32 26.35 38.08 27.55 ;
		RECT	0 26.35 0.32 27.55 ;
		RECT	38.08 26.35 38.4 27.55 ;
		RECT	0.32 28.32 38.08 28.39 ;
		RECT	0 28.32 0.32 28.39 ;
		RECT	38.08 28.32 38.4 28.39 ;
		RECT	0.32 29.19 38.08 30.39 ;
		RECT	0 29.19 0.32 30.39 ;
		RECT	38.08 29.19 38.4 30.39 ;
		RECT	0.32 31.16 38.08 31.23 ;
		RECT	0 31.16 0.32 31.23 ;
		RECT	38.08 31.16 38.4 31.23 ;
		RECT	0.32 32.03 38.08 32.545 ;
		RECT	0 32.03 0.32 32.545 ;
		RECT	38.08 32.03 38.4 32.545 ;
		RECT	0.32 33.195 38.08 33.29 ;
		RECT	0 33.195 0.32 33.29 ;
		RECT	38.08 33.195 38.4 33.29 ;
		RECT	0.32 33.52 38.08 33.65 ;
		RECT	0 33.52 0.32 33.65 ;
		RECT	38.08 33.52 38.4 33.65 ;
		RECT	0.32 34.06 38.08 34.535 ;
		RECT	0 34.06 0.32 34.535 ;
		RECT	38.08 34.06 38.4 34.535 ;
		RECT	0.32 35.64 38.08 35.975 ;
		RECT	0 35.64 0.32 35.975 ;
		RECT	38.08 35.64 38.4 35.975 ;
		RECT	0.32 36.635 38.08 37.04 ;
		RECT	0 36.635 0.32 36.82 ;
		RECT	38.08 36.635 38.4 37.04 ;
		RECT	0.32 37.35 38.08 37.435 ;
		RECT	0 37.35 0.32 37.435 ;
		RECT	38.08 37.35 38.4 37.435 ;
		RECT	0.32 37.665 38.08 38.145 ;
		RECT	0 37.665 0.32 38.145 ;
		RECT	38.08 37.665 38.4 38.145 ;
		RECT	0.32 38.82 38.08 38.885 ;
		RECT	0 38.82 0.32 38.885 ;
		RECT	38.08 38.82 38.4 38.885 ;
		RECT	0.32 39.295 38.08 39.735 ;
		RECT	0 39.295 0.32 39.735 ;
		RECT	38.08 39.295 38.4 39.735 ;
		RECT	0.32 39.965 38.08 40.3 ;
		RECT	0 39.965 0.32 40.3 ;
		RECT	38.08 39.965 38.4 40.3 ;
		RECT	0.32 40.71 38.08 40.855 ;
		RECT	0 40.71 0.32 40.855 ;
		RECT	38.08 40.71 38.4 40.855 ;
		RECT	0.32 41.775 38.08 42.89 ;
		RECT	0 41.775 0.32 42.89 ;
		RECT	38.08 41.775 38.4 42.89 ;
		RECT	0.32 43.3 38.08 43.86 ;
		RECT	0 43.3 0.32 43.86 ;
		RECT	38.08 43.3 38.4 43.86 ;
		RECT	0.32 44.27 38.08 45.42 ;
		RECT	0 44.27 0.32 45.42 ;
		RECT	38.08 44.27 38.4 45.42 ;
		RECT	0.32 46.04 38.08 46.28 ;
		RECT	0 46.04 0.32 46.28 ;
		RECT	38.08 46.04 38.4 46.28 ;
		RECT	0.32 46.69 38.08 47 ;
		RECT	0 46.69 0.32 47 ;
		RECT	38.08 46.69 38.4 47 ;
		RECT	0.32 47.23 38.08 47.31 ;
		RECT	0 47.23 0.32 47.31 ;
		RECT	38.08 47.23 38.4 47.31 ;
		RECT	0.32 47.72 38.08 48.075 ;
		RECT	0 47.72 0.32 48.075 ;
		RECT	38.08 47.72 38.4 48.075 ;
		RECT	0.32 48.735 38.08 48.915 ;
		RECT	0 48.735 0.32 48.915 ;
		RECT	38.08 48.735 38.4 48.915 ;
		RECT	0.32 49.325 38.08 49.39 ;
		RECT	0 49.325 0.32 49.39 ;
		RECT	38.08 49.325 38.4 49.39 ;
		RECT	0.32 49.8 38.08 49.955 ;
		RECT	0 49.8 0.32 49.955 ;
		RECT	38.08 49.8 38.4 49.955 ;
		RECT	0.32 50.265 38.08 50.655 ;
		RECT	0 50.265 0.32 50.655 ;
		RECT	38.08 50.265 38.4 50.655 ;
		RECT	0.32 51.065 38.08 51.195 ;
		RECT	0 51.065 0.32 51.195 ;
		RECT	38.08 51.065 38.4 51.195 ;
		RECT	0.32 51.425 38.08 51.85 ;
		RECT	0 51.425 0.32 51.85 ;
		RECT	38.08 51.425 38.4 51.85 ;
		RECT	0.32 52.26 38.08 52.37 ;
		RECT	0 52.26 0.32 52.37 ;
		RECT	38.08 52.26 38.4 52.37 ;
		RECT	0.32 53.155 38.08 53.215 ;
		RECT	0 53.155 0.32 53.215 ;
		RECT	38.08 53.155 38.4 53.215 ;
		RECT	0.32 53.87 38.08 53.96 ;
		RECT	0 53.87 0.32 53.96 ;
		RECT	38.08 53.87 38.4 53.96 ;
		RECT	0.32 54.61 38.08 54.715 ;
		RECT	0 54.61 0.32 54.715 ;
		RECT	38.08 54.61 38.4 54.715 ;
		RECT	0.32 55.515 38.08 55.585 ;
		RECT	0 55.515 0.32 55.585 ;
		RECT	38.08 55.515 38.4 55.585 ;
		RECT	0.32 56.355 38.08 57.555 ;
		RECT	0 56.355 0.32 57.555 ;
		RECT	38.08 56.355 38.4 57.555 ;
		RECT	0.32 58.355 38.08 58.425 ;
		RECT	0 58.355 0.32 58.425 ;
		RECT	38.08 58.355 38.4 58.425 ;
		RECT	0.32 59.195 38.08 60.395 ;
		RECT	0 59.195 0.32 60.395 ;
		RECT	38.08 59.195 38.4 60.395 ;
		RECT	0.32 61.195 38.08 61.265 ;
		RECT	0 61.195 0.32 61.265 ;
		RECT	38.08 61.195 38.4 61.265 ;
		RECT	0.32 62.035 38.08 63.235 ;
		RECT	0 62.035 0.32 63.235 ;
		RECT	38.08 62.035 38.4 63.235 ;
		RECT	0.32 64.035 38.08 64.105 ;
		RECT	0 64.035 0.32 64.105 ;
		RECT	38.08 64.035 38.4 64.105 ;
		RECT	0.32 64.875 38.08 66.075 ;
		RECT	0 64.875 0.32 66.075 ;
		RECT	38.08 64.875 38.4 66.075 ;
		RECT	0.32 66.875 38.08 66.945 ;
		RECT	0 66.875 0.32 66.945 ;
		RECT	38.08 66.875 38.4 66.945 ;
		RECT	0.32 67.715 38.08 68.915 ;
		RECT	0 67.715 0.32 68.915 ;
		RECT	38.08 67.715 38.4 68.915 ;
		RECT	0.32 69.715 38.08 69.785 ;
		RECT	0 69.715 0.32 69.785 ;
		RECT	38.08 69.715 38.4 69.785 ;
		RECT	0.32 70.555 38.08 71.755 ;
		RECT	0 70.555 0.32 71.755 ;
		RECT	38.08 70.555 38.4 71.755 ;
		RECT	0.32 72.555 38.08 72.625 ;
		RECT	0 72.555 0.32 72.625 ;
		RECT	38.08 72.555 38.4 72.625 ;
		RECT	0.32 73.395 38.08 74.595 ;
		RECT	0 73.395 0.32 74.595 ;
		RECT	38.08 73.395 38.4 74.595 ;
		RECT	0.32 75.395 38.08 75.465 ;
		RECT	0 75.395 0.32 75.465 ;
		RECT	38.08 75.395 38.4 75.465 ;
		RECT	0.32 76.235 38.08 77.435 ;
		RECT	0 76.235 0.32 77.435 ;
		RECT	38.08 76.235 38.4 77.435 ;
		RECT	0.32 78.235 38.08 78.305 ;
		RECT	0 78.235 0.32 78.305 ;
		RECT	38.08 78.235 38.4 78.305 ;
		RECT	0.32 79.075 38.08 80.275 ;
		RECT	0 79.075 0.32 80.275 ;
		RECT	38.08 79.075 38.4 80.275 ;
		RECT	0.32 81.075 38.08 81.145 ;
		RECT	0 81.075 0.32 81.145 ;
		RECT	38.08 81.075 38.4 81.145 ;
		RECT	0.32 81.915 38.08 83.115 ;
		RECT	0 81.915 0.32 83.115 ;
		RECT	38.08 81.915 38.4 83.115 ;
		RECT	0.32 83.915 38.08 83.985 ;
		RECT	0 83.915 0.32 83.985 ;
		RECT	38.08 83.915 38.4 83.985 ;
		RECT	0.32 84.755 38.08 85.955 ;
		RECT	0 84.755 0.32 85.955 ;
		RECT	38.08 84.755 38.4 85.955 ;
		RECT	0.32 86.755 38.08 86.825 ;
		RECT	0 86.755 0.32 86.825 ;
		RECT	38.08 86.755 38.4 86.825 ;
		RECT	0.32 87.595 38.08 88.685 ;
		RECT	0 87.595 0.32 88.685 ;
		RECT	38.08 87.595 38.4 88.685 ;
		RECT	0.32 89.495 38.08 89.585 ;
		RECT	0 89.495 0.32 89.585 ;
		RECT	38.08 89.495 38.4 89.585 ;
		LAYER	VIA1 DESIGNRULEWIDTH 0.07 ;
		RECT	0 0 38.4 89.585 ;
		LAYER	VIA2 DESIGNRULEWIDTH 0.07 ;
		RECT	0 0 38.4 89.585 ;
		LAYER	VIA3 DESIGNRULEWIDTH 0.07 ;
		RECT	0 0 38.4 89.585 ;
	END

END sram128x46

END LIBRARY

